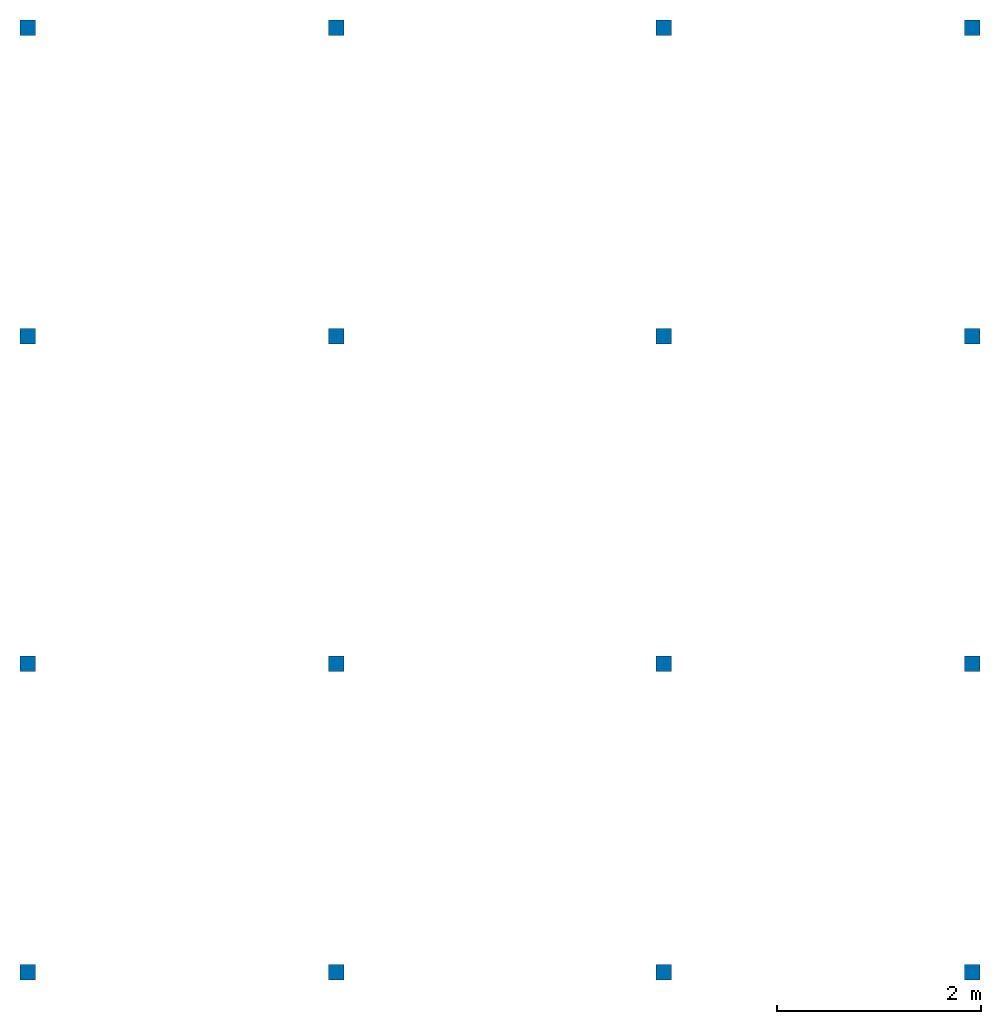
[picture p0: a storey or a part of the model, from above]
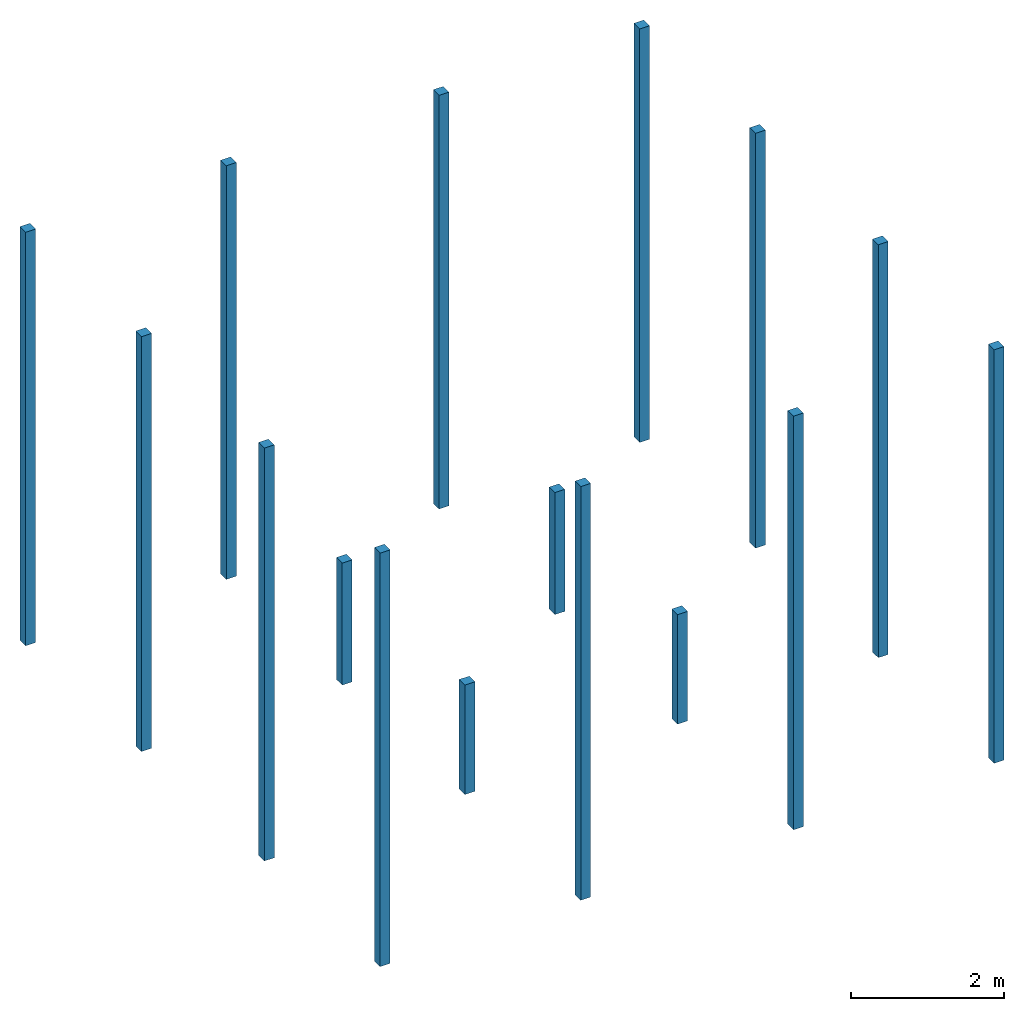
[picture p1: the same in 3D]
Properties of the parts of a building model (IFC2X3), part 1 of 2

# File
Description: ViewDefinition [CoordinationView_V2.0, QuantityTakeOffAddOnView], RevitIdentifiers [ContentGUID: 1b7e957a-3815-4cde-909e-a2956a1124d2, VersionGUID: 607071c9-a920-4b14-b0dc-eb4321b22190, NumberOfSaves: 63], CoordinateReference [CoordinateBase: Coordenadas compartidas, ProjectSite: Default Site]
File name: 20261019_WorkshopBIM-IA_AlbertoJercicM_.ifc
Time: 2026-10-19T21:17:42-04:00
Written by: ODA SDAI 24.12
Made in: Autodesk Revit 25.4.41.14 (ESP) - IFC 25.4.41.14

# IfcProject, TBC-AJ-01
LongName: Habitáculo y Refugio Turístico Magallanes; Phase: Caso de Estudio Académico

# IfcSite, Default
RefLatitude: 42, 21, 31, 181945; RefLongitude: -71, -3, -24, -263305; RefElevation: 0 cm
Otros - Categoría: Información de proyecto; Dirección de proyecto: Tierra del Fuego, Región de Magallanes, Chile.; Estado de proyecto: Caso de Estudio Académico; Fecha de emisión de proyecto: 2026; Nombre de cliente: The BIM COWORK; Nombre de proyecto: Habitáculo y Refugio Turístico Magallanes; Número de proyecto: TBC-AJ-01
Datos de identidad - Autor: CASO DE ESTUDIO — Únicamente con fines académicos. No apto para construcción. Proyecto liberado por caso de estudio TBC.; Descripción de organización: Estudiante: Arq Alberto Jercic | Curso: BIM Aplicado — Módulo IV | CASO DE ESTUDIO — Únicamente con fines académicos. No apto para construcción. Proyecto liberado por caso de estudio TBC.; Nombre del edificio: Workshop Hbaitáculo - Refugio Tierra del Fuego; Nombre de organización: The Bim Cowork

# IfcSite: Sólido topográfico:Sólido topográfico 1, Sólido topográfico:Sólido topográfico 1:651923
Type - Material: Earth 250 cm
Type - Otros - Categoría: Sólido topográfico; Nombre de familia: Sólido topográfico
Type - Construcción - Grosor predeterminado: 250 cm
Type - Gráficos - Color de relleno de detalle bajo: 0
Type - Datos de identidad - Descripción: Terreno / emplazamiento.; Marca de tipo: TP1; Nombre de tipo: Sólido topográfico 1; Nota clave: TP1
Type - Propiedades analíticas - Absortancia: 0.1; Aspereza: 1; Coeficiente de transferencia de calor (U): 0.3348 kg/s3/K; Masa térmica: 3399500 kg/K/s2; Resistencia térmica (R): 2.98686 s3*K/kg
Pset_LandRegistration - LandTitleID: S/I
Pset_PropertyAgreement - Restrictions: S/I
Pset_SiteCommon - SeismicClassification: S/I
BaseQuantities - GrossArea: 40.8669 m2
Otros - Familia: Sólido topográfico; Familia y tipo: Sólido topográfico: Sólido topográfico 1; ID de tipo: 421453; Tipo: Sólido topográfico 1
Restricciones - Delimitación de habitación: yes; Relacionado con masa: no; Desfase de altura desde nivel: 0 cm; Nivel: NTN
Datos - NDI: NDI-1
Cotas - Área: 576.228 m2; Elevación en parte inferior: -250 cm; Perímetro: 9600 cm; Volumen: 935.852 m3
Proceso por fases - Fase de creación: New Construction
Edición de forma de losa - Condición de borde curvado: 0

# IfcBuilding, Workshop Hbaitáculo - Refugio Tierra del Fuego
LongName: Workshop Hbaitáculo - Refugio Tierra del Fuego
Otros - Categoría: Información de proyecto; Dirección de proyecto: Tierra del Fuego, Región de Magallanes, Chile.; Estado de proyecto: Caso de Estudio Académico; Fecha de emisión de proyecto: 2026; Nombre de cliente: The BIM COWORK; Nombre de proyecto: Habitáculo y Refugio Turístico Magallanes; Número de proyecto: TBC-AJ-01
Datos de identidad - Autor: CASO DE ESTUDIO — Únicamente con fines académicos. No apto para construcción. Proyecto liberado por caso de estudio TBC.; Descripción de organización: Estudiante: Arq Alberto Jercic | Curso: BIM Aplicado — Módulo IV | CASO DE ESTUDIO — Únicamente con fines académicos. No apto para construcción. Proyecto liberado por caso de estudio TBC.; Nombre del edificio: Workshop Hbaitáculo - Refugio Tierra del Fuego; Nombre de organización: The Bim Cowork

# IfcBuildingStorey: Nivel:TBC-NIVEL (6)
In: Workshop Hbaitáculo - Refugio Tierra del Fuego
Otros - Categoría: Niveles; Familia: Nivel; Familia y tipo: Nivel: TBC-NIVEL; ID de tipo: 365066; Tipo: TBC-NIVEL
Cotas - Altura de cálculo: 0 cm
Datos de identidad - Estructura: no; Planta de edificio: yes
Otros(Tipo) - Categoría: Niveles; Nombre de familia: Nivel
Restricciones(Tipo) - Base de elevación: Punto base del proyecto
Gráficos(Tipo) - Color: 8421504; Grosor de línea: 1; Patrón de línea: Centre; Símbolo: NVL_Cabezal Nivel Triangulo1 : 2,0 mm; Símbolo en extremo 1 por defecto: yes; Símbolo en extremo 2 por defecto: no
Datos de identidad(Tipo) - Nombre de tipo: TBC-NIVEL
Name | LongName = Nombre | Elevation (cm) = Elevación (cm)
NOG_BASE PILARES | NOG_BASE PILARES | -180
NTN | NTN | 0
NOG_PISO 1 | NOG_PISO 1 | 100
NPT | NPT | 123
NOG_SIP Cara Superior | NOG_SIP Cara Superior | 421
NOG_Pilares Cara Superior | NOG_Pilares Cara Superior | 601

# IfcSpace: Baño 1 2:740895, 2
In: NPT
LongName: Baño 1; InteriorOrExteriorSpace: INTERNAL
Pset_SpaceCommon - IsExternal: no
Pset_SpaceFireSafetyRequirements - FireRiskFactor: Sin informacion
BaseQuantities - GrossFloorArea: 1.95108 m2; NetFloorArea: 1.95108 m2; GrossCeilingArea: 1.95108 m2; Height: 295.421 cm; GrossVolume: 5.76388 m3
Otros - Categoría: Habitaciones; ID de fase: 86961
Restricciones - Desfase de base: 0 cm; Límite superior: NOG_SIP Cara Superior; Desfase de límite: -2.57916 cm; Nivel: NPT
Datos - NDI: NDI-1
Cotas - Altura de cálculo: 0 cm; Altura sin límites: 295.421 cm; Área: 1.95108 m2; Perímetro: 561 cm; Volumen: 5.76388 m3
Análisis energético - Carga de iluminación base en: Por tipo de espacio; Carga de iluminación especificada: 0 W; Carga de iluminación real: 0 W; Carga de potencia base de diseño en: Por tipo de espacio; Carga de potencia especificada: 0 W; Carga de potencia real: 0 W; Contribución de iluminación de plénum: 0.2; Número de personas: 0; Unidades de carga de iluminación: Densidad de potencia; Unidades de carga de potencia: Densidad de potencia; Valores de carga de calor: Por tipo de espacio; Área por persona: 28.5714 m2; Carga de iluminación especificada por área: 10.7639 kg/s3; Carga de iluminación real por área: 0 kg/s3; Carga de potencia especificada por área: 13.9931 kg/s3; Carga de potencia real por área: 0 kg/s3; Incremento de calor latente por persona: 58.6142 W; Incremento de calor sensible por persona: 73.2678 W; Incremento de calor total por persona: 131.882 W
Datos de identidad - Altura: 295.421 cm; Area bruta del espacio: 1.95108 m2; Area neta del espacio: 1.95108 m2; Factor de riesgo de incendio: Sin informacion; Nombre: Baño 1; Nombre descriptivo del espacio: BANO_1; Nombre o codigo del Espacio: 2; Número: 2; Perimetro: 561 cm; Volumen: 5.76388 m3
Proceso por fases - Fase: New Construction
Texto - Descripción Acabado de Cielo: Cielo Placa Volcanita ST + Melamina; Descripción Acabado de Muros: Rev. Porcelanato ZH; Descripción Acabado de Piso: PAV Tipo Porcelanato 1; Descripción Guardapolvo: No considera

# IfcSpace: Baño 2 3:740898, 3
In: NPT
LongName: Baño 2; InteriorOrExteriorSpace: INTERNAL
Pset_SpaceCommon - IsExternal: no
Pset_SpaceFireSafetyRequirements - FireRiskFactor: Sin informacion
BaseQuantities - GrossFloorArea: 1.9488 m2; NetFloorArea: 1.9488 m2; GrossCeilingArea: 1.9488 m2; Height: 295.616 cm; GrossVolume: 5.7587 m3
Otros - Categoría: Habitaciones; ID de fase: 86961
Restricciones - Desfase de base: 0 cm; Límite superior: NOG_SIP Cara Superior; Desfase de límite: -2.3836 cm; Nivel: NPT
Datos - NDI: NDI-1
Cotas - Altura de cálculo: 0 cm; Altura sin límites: 295.616 cm; Área: 1.9488 m2; Perímetro: 561 cm; Volumen: 5.7587 m3
Análisis energético - Carga de iluminación base en: Por tipo de espacio; Carga de iluminación especificada: 0 W; Carga de iluminación real: 0 W; Carga de potencia base de diseño en: Por tipo de espacio; Carga de potencia especificada: 0 W; Carga de potencia real: 0 W; Contribución de iluminación de plénum: 0.2; Número de personas: 0; Unidades de carga de iluminación: Densidad de potencia; Unidades de carga de potencia: Densidad de potencia; Valores de carga de calor: Por tipo de espacio; Área por persona: 28.5714 m2; Carga de iluminación especificada por área: 10.7639 kg/s3; Carga de iluminación real por área: 0 kg/s3; Carga de potencia especificada por área: 13.9931 kg/s3; Carga de potencia real por área: 0 kg/s3; Incremento de calor latente por persona: 58.6142 W; Incremento de calor sensible por persona: 73.2678 W; Incremento de calor total por persona: 131.882 W
Datos de identidad - Altura: 295.616 cm; Area bruta del espacio: 1.9488 m2; Area neta del espacio: 1.9488 m2; Factor de riesgo de incendio: Sin informacion; Nombre: Baño 2; Nombre descriptivo del espacio: BANO_2; Nombre o codigo del Espacio: 3; Número: 3; Perimetro: 561 cm; Volumen: 5.7587 m3
Proceso por fases - Fase: New Construction
Texto - Descripción Acabado de Cielo: Cielo Placa Volcanita ST + Melamina; Descripción Acabado de Muros: Rev. Porcelanato ZH; Descripción Acabado de Piso: PAV Tipo Porcelanato 1; Descripción Guardapolvo: No considera

# IfcSpace: Cocina 4:741249, 4
In: NPT
LongName: Cocina; InteriorOrExteriorSpace: INTERNAL
Pset_SpaceCommon - IsExternal: no
Pset_SpaceFireSafetyRequirements - FireRiskFactor: Sin informacion
BaseQuantities - GrossFloorArea: 8.67247 m2; NetFloorArea: 8.67247 m2; GrossCeilingArea: 8.67247 m2; Height: 298 cm
Otros - Categoría: Habitaciones; ID de fase: 86961
Restricciones - Desfase de base: 0 cm; Límite superior: NOG_SIP Cara Superior; Desfase de límite: 0 cm; Nivel: NPT
Datos - NDI: NDI-1
Cotas - Altura de cálculo: 0 cm; Altura sin límites: 298 cm; Área: 8.67247 m2; Perímetro: 1179.9 cm; Volumen: 22.599 m3
Análisis energético - Carga de iluminación base en: Por tipo de espacio; Carga de iluminación especificada: 0 W; Carga de iluminación real: 0 W; Carga de potencia base de diseño en: Por tipo de espacio; Carga de potencia especificada: 0 W; Carga de potencia real: 0 W; Contribución de iluminación de plénum: 0.2; Número de personas: 0; Unidades de carga de iluminación: Densidad de potencia; Unidades de carga de potencia: Densidad de potencia; Valores de carga de calor: Por tipo de espacio; Área por persona: 28.5714 m2; Carga de iluminación especificada por área: 10.7639 kg/s3; Carga de iluminación real por área: 0 kg/s3; Carga de potencia especificada por área: 13.9931 kg/s3; Carga de potencia real por área: 0 kg/s3; Incremento de calor latente por persona: 58.6142 W; Incremento de calor sensible por persona: 73.2678 W; Incremento de calor total por persona: 131.882 W
Datos de identidad - Altura: 298 cm; Area bruta del espacio: 8.67247 m2; Area neta del espacio: 8.67247 m2; Factor de riesgo de incendio: Sin informacion; Nombre: Cocina; Nombre descriptivo del espacio: COCINA; Nombre o codigo del Espacio: 4; Número: 4; Perimetro: 1179.9 cm; Volumen: 22.599 m3
Proceso por fases - Fase: New Construction
Texto - Descripción Acabado de Cielo: Cielo Placa Volcanita ST + Melamina; Descripción Acabado de Muros: Rev. Melamina tipo madera; Descripción Acabado de Piso: PAV Tipo Madera; Descripción Guardapolvo: No considera

# IfcSpace: Espacio central 1:740673, 1
In: NPT
LongName: Espacio central; InteriorOrExteriorSpace: INTERNAL
Pset_SpaceCommon - IsExternal: no
Pset_SpaceFireSafetyRequirements - FireRiskFactor: Sin informacion
BaseQuantities - GrossFloorArea: 53.2464 m2; NetFloorArea: 53.2464 m2; GrossCeilingArea: 53.2464 m2; Height: 295 cm; GrossVolume: 157.077 m3
Otros - Categoría: Habitaciones; ID de fase: 86961
Restricciones - Desfase de base: 0 cm; Desfase de límite: -3 cm; Límite superior: NOG_SIP Cara Superior; Nivel: NPT
Datos - NDI: NDI-1
Cotas - Altura de cálculo: 0 cm; Altura sin límites: 295 cm; Área: 53.2464 m2; Perímetro: 5125.3 cm; Volumen: 157.077 m3
Análisis energético - Área por persona: 28.5714 m2; Carga de iluminación base en: Por tipo de espacio; Carga de iluminación especificada: 0 W; Carga de iluminación especificada por área: 10.7639 kg/s3; Carga de iluminación real: 0 W; Carga de iluminación real por área: 0 kg/s3; Carga de potencia base de diseño en: Por tipo de espacio; Carga de potencia especificada: 0 W; Carga de potencia especificada por área: 13.9931 kg/s3; Carga de potencia real: 0 W; Carga de potencia real por área: 0 kg/s3; Contribución de iluminación de plénum: 0.2; Incremento de calor latente por persona: 58.6142 W; Incremento de calor sensible por persona: 73.2678 W; Incremento de calor total por persona: 131.882 W; Número de personas: 0; Unidades de carga de iluminación: Densidad de potencia; Unidades de carga de potencia: Densidad de potencia; Valores de carga de calor: Por tipo de espacio
Datos de identidad - Altura: 295 cm; Area bruta del espacio: 53.2464 m2; Area neta del espacio: 53.2464 m2; Factor de riesgo de incendio: Sin informacion; Nombre: Espacio central; Nombre descriptivo del espacio: ESPACIO_CENTRAL; Nombre o codigo del Espacio: 1; Número: 1; Perimetro: 5125.3 cm; Volumen: 157.077 m3
Proceso por fases - Fase: New Construction
Texto - Descripción Acabado de Cielo: Cielo Placa Volcanita ST + Melamina; Descripción Acabado de Muros: Rev. Melamina tipo madera; Descripción Acabado de Piso: PAV Tipo Madera; Descripción Guardapolvo: No considera

# IfcBeam: Arauco Hilam Viga:Hilam Viga 65x228 mm (53)
Type - PredefinedType: BEAM
Type - Otros - Categoría: Armazón estructural; Nombre de familia: Arauco Hilam Viga
Type - Cotas - CA_Ancho: 22.8 cm; CA_Espesor: 6.5 cm; CA_Largo: 800 cm
Type - Datos de identidad - Ca_Ancho: 228mm; ca_Certificaciones: Norma Chilena NCh2148; ca_Código_Catálogo_Arquitectura: 231_ARA_017; ca_Contacto: Especificaciones@arauco.cl; ca_Creado_por: Catálogo Arquitectura; ca_Especificaciones_Técnicas: Hilam Estándar es una línea de productos de ingeniería para la construcción, conformada por elementos de madera laminada de sección estándar que se complementa con otros productos de madera y tableros de ARAUCO®. Además, se puede usar en estructuras mixtas, combinado con otros materiales como hormigón armado y acero.; Ca_Espesores: 65mm; ca_Fabricante: Arauco; Ca_Instalación: No se especifica; ca_Itemizado_CDT: C 06 02 00; Ca_Largo: 8m; ca_MasterFormat®: 06 18 13; ca_Países_de_distribución: Ar/Au/Ch/Co/EU/Me/Pe/USA/Ca; Ca_Peso: 65kg; Ca_Piezas por paquete: 20; ca_Producto: Hilam Viga 65x228mm; ca_Representante: Arauco; ca_Teléfono: 56 2 24617 200; Ca_Usos: Vigas de piso y techo. Pilares a la vista. Pérgolas. Cobertizos. Escaleras. Decoración. Area industrial.; ca_Web_del_fabricante: www.arauco.cl; ca_Web_del_Representante: www.arauco.cl; Descripción: Viga madera laminada encolada Hilam 65x228 mm NCh2148. Madera expuesta con tratamiento: protector impregnante / stain (uso general exterior) Ceresita Cerestain.; Marca de tipo: VG1; Nombre de tipo: Hilam Viga 65x228 mm; Nota clave: VIG; Número OmniClass: 23.25.30.11.14.14; Título OmniClass: Beams
Type - Estructura - Forma de sección: 0
Material: Madera Oscura
BaseQuantities - CrossSectionArea: 0.01482 m2
Pset_BeamCommon - FireRating: S/I; LoadBearing: yes; Status: NEW
Otros - Familia: Arauco Hilam Viga; Familia y tipo: Arauco Hilam Viga: Hilam Viga 65x228 mm; ID de tipo: 581389; Tipo: Hilam Viga 65x228 mm
Restricciones - Rotación de sección transversal: 0 deg
Datos - NDI: NDI-1
Datos de identidad - Tiene asociación: no
Materiales y acabados - Material estructural: Madera Oscura
Proceso por fases - Fase de creación: New Construction
Estructura - Recubrimiento de armadura - Cara inferior: Rebar Cover 1 <25 mm>; Recubrimiento de armadura - Cara superior: Rebar Cover 1 <25 mm>; Recubrimiento de armadura - Otras caras: Rebar Cover 1 <25 mm>; Uso estructural: Otro
Posición geométrica - Estado de unión: Ambas uniones activadas; Justificación Y: Origen; Justificación YZ: Uniforme; Justificación Z: Parte superior; Valor de desfase Y: 0 cm; Valor de desfase Z: 0 cm
Name (Arauco Hilam Viga:Hilam Viga 65x228 mm:...) | In | Length (cm) = Longitud de corte (cm) | OuterSurfaceArea (m2) | GrossVolume (m3) = NetVolume (m3) = Volumen (m3) | Desfase de nivel final (cm) | Desfase de nivel inicial (cm) | Elevación de nivel de referencia (cm) | Nivel de referencia | Elevación en parte inferior (cm) | Elevación en parte superior (cm) | Longitud (cm) | Extensión final (cm) | Extensión inicial (cm)
581417 | NOG_PISO 1 | 930 | 5.4498 | 0.137826 | 0 | 0 | 100 | NOG_PISO 1 | 77.2 | 100 | 961.251 | 0 | -31.2511 | Restricciones - Orientación: Normal; Plano de trabajo: Nivel : NOG_PISO 1
581750 | NOG_PISO 1 | 930 | 5.4498 | 0.137826 | 0 | 0 | 100 | NOG_PISO 1 | 77.2 | 100 | 961.251 | 0 | -31.2511 | Restricciones - Orientación: Normal; Plano de trabajo: Nivel : NOG_PISO 1
581929 | NOG_PISO 1 | 318.25 | 1.86494 | 0.0471646 | 0 | 0 | 100 | NOG_PISO 1 | 77.2 | 100 | 349.501 | 0 | -31.2511 | Restricciones - Orientación: Normal; Plano de trabajo: Nivel : NOG_PISO 1
581937 | NOG_PISO 1 | 318.25 | 1.86494 | 0.0471646 | 0 | 0 | 100 | NOG_PISO 1 | 77.2 | 100 | 349.501 | 0 | -31.2511 | Restricciones - Orientación: Normal; Plano de trabajo: Nivel : NOG_PISO 1
581945 | NOG_PISO 1 | 318.25 | 1.86494 | 0.0471646 | 0 | 0 | 100 | NOG_PISO 1 | 77.2 | 100 | 349.501 | 0 | -31.2511 | Restricciones - Orientación: Normal; Plano de trabajo: Nivel : NOG_PISO 1
582254 | NOG_PISO 1 | 930 | 5.4498 | 0.137826 | 0 | 0 | 100 | NOG_PISO 1 | 77.2 | 100 | 961.251 | 0 | -31.2511 | Restricciones - Orientación: Normal; Plano de trabajo: Nivel : NOG_PISO 1
582255 | NOG_PISO 1 | 930 | 5.4498 | 0.137826 | 0 | 0 | 100 | NOG_PISO 1 | 77.2 | 100 | 961.251 | 0 | -31.2511 | Restricciones - Orientación: Normal; Plano de trabajo: Nivel : NOG_PISO 1
582256 | NOG_PISO 1 | 930 | 5.4498 | 0.137826 | 0 | 0 | 100 | NOG_PISO 1 | 77.2 | 100 | 961.251 | 0 | -31.2511 | Restricciones - Orientación: Normal; Plano de trabajo: Nivel : NOG_PISO 1
582427 | NOG_PISO 1 | 930 | 5.4498 | 0.137826 | 0 | 0 | 100 | NOG_PISO 1 | 77.2 | 100 | 961.251 | 0 | -31.2511 | Restricciones - Orientación: Normal; Plano de trabajo: Nivel : NOG_PISO 1
582686 | NOG_PISO 1 | 930 | 5.4498 | 0.137826 | 0 | 0 | 100 | NOG_PISO 1 | 77.2 | 100 | 961.251 | 0 | -31.2511 | Restricciones - Orientación: Normal; Plano de trabajo: Nivel : NOG_PISO 1
582687 | NOG_PISO 1 | 930 | 5.4498 | 0.137826 | 0 | 0 | 100 | NOG_PISO 1 | 77.2 | 100 | 961.251 | 0 | -31.2511 | Restricciones - Orientación: Normal; Plano de trabajo: Nivel : NOG_PISO 1
582688 | NOG_PISO 1 | 930 | 5.4498 | 0.137826 | 0 | 0 | 100 | NOG_PISO 1 | 77.2 | 100 | 961.251 | 0 | -31.2511 | Restricciones - Orientación: Normal; Plano de trabajo: Nivel : NOG_PISO 1
582689 | NOG_PISO 1 | 930 | 5.4498 | 0.137826 | 0 | 0 | 100 | NOG_PISO 1 | 77.2 | 100 | 961.251 | 0 | -31.2511 | Restricciones - Orientación: Normal; Plano de trabajo: Nivel : NOG_PISO 1
582690 | NOG_PISO 1 | 930 | 5.4498 | 0.137826 | 0 | 0 | 100 | NOG_PISO 1 | 77.2 | 100 | 961.251 | 0 | -31.2511 | Restricciones - Orientación: Normal; Plano de trabajo: Nivel : NOG_PISO 1
583638 | NOG_PISO 1 | 966.668 | 5.66467 | 0.14326 | -22.8 | -22.8 | 100 | NOG_PISO 1 | 54.4 | 77.2 | 952 | -9.89385 | 24.5614
584148 | NOG_PISO 1 | 956.862 | 5.60721 | 0.141807 | -45.6 | -45.6 | 100 | NOG_PISO 1 | 31.6 | 54.4 | 1110 | -87.3622 | -65.7763
589290 | NOG_PISO 1 | 956.862 | 5.60721 | 0.141807 | -45.6 | -45.6 | 100 | NOG_PISO 1 | 31.6 | 54.4 | 1110 | -87.3622 | -65.7763
589528 | NOG_PISO 1 | 966.668 | 5.66467 | 0.14326 | -22.8 | -22.8 | 100 | NOG_PISO 1 | 54.4 | 77.2 | 952 | -9.89385 | 24.5614
589572 | NOG_PISO 1 | 966.668 | 5.66467 | 0.14326 | -22.8 | -22.8 | 100 | NOG_PISO 1 | 54.4 | 77.2 | 952 | -9.89385 | 24.5614
589573 | NOG_PISO 1 | 966.668 | 5.66467 | 0.14326 | -22.8 | -22.8 | 100 | NOG_PISO 1 | 54.4 | 77.2 | 952 | -9.89385 | 24.5614
589663 | NOG_PISO 1 | 956.862 | 5.60721 | 0.141807 | -45.6 | -45.6 | 100 | NOG_PISO 1 | 31.6 | 54.4 | 1110 | -87.3622 | -65.7763
589673 | NOG_PISO 1 | 956.862 | 5.60721 | 0.141807 | -45.6 | -45.6 | 100 | NOG_PISO 1 | 31.6 | 54.4 | 1110 | -87.3622 | -65.7763
593334 | NOG_SIP Cara Superior | 956.862 | 5.60721 | 0.141807 | 107.2 | 107.2 | 421 | NOG_SIP Cara Superior | 505.4 | 528.2 | 1110 | -87.3622 | -65.7763
593451 | NOG_Pilares Cara Superior | 956.862 | 5.60721 | 0.141807 | -22.8 | -22.8 | 601 | NOG_Pilares Cara Superior | 555.4 | 578.2 | 1110 | -87.3622 | -65.7763
593488 | NOG_PISO 1 | 1184.63 | 6.94193 | 0.175562 | 502 | 452 | 100 | NOG_PISO 1 |  |  | 953.312 | 98.1433 | 133.175
594363 | NOG_Pilares Cara Superior | 1026.86 | 6.01741 | 0.152181 | -40 | -40 | 601 | NOG_Pilares Cara Superior | 538.2 | 561 | 1110 | -17.3622 | -65.7763
594373 | NOG_Pilares Cara Superior | 956.862 | 5.60721 | 0.141807 | -55.5 | -55.5 | 601 | NOG_Pilares Cara Superior | 522.7 | 545.5 | 1110 | -87.3622 | -65.7763
595492 | NOG_PISO 1 | 1093 | 6.40498 | 0.161983 | 491.21 | 491.21 | 100 | NOG_PISO 1 | 568.41 | 591.21 | 961.251 | 163 | -31.2511
595493 | NOG_PISO 1 | 1093 | 6.40498 | 0.161983 | 503.02 | 503.02 | 100 | NOG_PISO 1 | 580.22 | 603.02 | 961.251 | 163 | -31.2511
595494 | NOG_PISO 1 | 1093 | 6.40498 | 0.161983 | 499.08 | 499.08 | 100 | NOG_PISO 1 | 576.28 | 599.08 | 961.251 | 163 | -31.2511
595495 | NOG_PISO 1 | 1093 | 6.40498 | 0.161983 | 495.14 | 495.14 | 100 | NOG_PISO 1 | 572.34 | 595.14 | 961.251 | 163 | -31.2511
595496 | NOG_PISO 1 | 1093 | 6.40498 | 0.161983 | 487.53 | 487.53 | 100 | NOG_PISO 1 | 564.73 | 587.53 | 961.251 | 163 | -31.2511
595497 | NOG_PISO 1 | 1093 | 6.40498 | 0.161983 | 483.85 | 483.85 | 100 | NOG_PISO 1 | 561.05 | 583.85 | 961.251 | 163 | -31.2511
595498 | NOG_PISO 1 | 1093 | 6.40498 | 0.161983 | 480.18 | 480.18 | 100 | NOG_PISO 1 | 557.38 | 580.18 | 961.251 | 163 | -31.2511
595499 | NOG_PISO 1 | 1093 | 6.40498 | 0.161983 | 476.5 | 476.5 | 100 | NOG_PISO 1 | 553.7 | 576.5 | 961.251 | 163 | -31.2511
595500 | NOG_PISO 1 | 1093 | 6.40498 | 0.161983 | 506.96 | 506.96 | 100 | NOG_PISO 1 | 584.16 | 606.96 | 961.251 | 163 | -31.2511
595501 | NOG_PISO 1 | 1093 | 6.40498 | 0.161983 | 510.64 | 510.64 | 100 | NOG_PISO 1 | 587.84 | 610.64 | 961.251 | 163 | -31.2511
595502 | NOG_PISO 1 | 1093 | 6.40498 | 0.161983 | 514.31 | 514.31 | 100 | NOG_PISO 1 | 591.51 | 614.31 | 961.251 | 163 | -31.2511
595503 | NOG_PISO 1 | 1093 | 6.40498 | 0.161983 | 517.99 | 517.99 | 100 | NOG_PISO 1 | 595.19 | 617.99 | 961.251 | 163 | -31.2511
595504 | NOG_PISO 1 | 1093 | 6.40498 | 0.161983 | 521.67 | 521.67 | 100 | NOG_PISO 1 | 598.87 | 621.67 | 961.251 | 163 | -31.2511
597168 | NOG_PISO 1 | 1184.63 | 6.94193 | 0.175562 | 502 | 452 | 100 | NOG_PISO 1 |  |  | 953.312 | 98.1433 | 133.175
597174 | NOG_PISO 1 | 1184.63 | 6.94193 | 0.175562 | 502 | 452 | 100 | NOG_PISO 1 |  |  | 953.312 | 98.1433 | 133.175
597198 | NOG_PISO 1 | 1184.63 | 6.94193 | 0.175562 | 502 | 452 | 100 | NOG_PISO 1 |  |  | 953.312 | 98.1433 | 133.175
598141 | NOG_PISO 1 | 1093 | 6.40498 | 0.161983 | 472.82 | 472.82 | 100 | NOG_PISO 1 | 550.02 | 572.82 | 961.251 | 163 | -31.2511
598283 | NOG_PISO 1 | 1093 | 6.40498 | 0.161983 | 469.15 | 469.15 | 100 | NOG_PISO 1 | 546.35 | 569.15 | 961.251 | 163 | -31.2511
598472 | NOG_PISO 1 | 1093 | 6.40498 | 0.161983 | 525.34 | 525.34 | 100 | NOG_PISO 1 | 602.54 | 625.34 | 961.251 | 163 | -31.2511
598478 | NOG_PISO 1 | 1093 | 6.40498 | 0.161983 | 529.02 | 529.02 | 100 | NOG_PISO 1 | 606.22 | 629.02 | 961.251 | 163 | -31.2511
637849 | NOG_PISO 1 | 318.25 | 1.86494 | 0.0471646 | 0 | 0 | 100 | NOG_PISO 1 | 77.2 | 100 | 318.25 | 0 | 0 | Restricciones - Orientación: Normal; Plano de trabajo: Nivel : NOG_PISO 1
637916 | NOG_PISO 1 | 318.25 | 1.86494 | 0.0471646 | 0 | 0 | 100 | NOG_PISO 1 | 77.2 | 100 | 441.251 | 0 | -123.001 | Restricciones - Orientación: Normal; Plano de trabajo: Nivel : NOG_PISO 1
638011 | NOG_PISO 1 | 318.25 | 1.86494 | 0.0471646 | 0 | 0 | 100 | NOG_PISO 1 | 77.2 | 100 | 318.25 | 0 | 0 | Restricciones - Orientación: Normal; Plano de trabajo: Nivel : NOG_PISO 1
658531 | NOG_SIP Cara Superior | 966.668 | 5.66467 | 0.14326 | 84.4 | 84.4 | 421 | NOG_SIP Cara Superior | 482.6 | 505.4 | 952 | -9.89385 | 24.5614
658533 | NOG_SIP Cara Superior | 956.862 | 5.60721 | 0.141807 | 61.6 | 61.6 | 421 | NOG_SIP Cara Superior | 459.8 | 482.6 | 1110 | -87.3622 | -65.7763
658534 | NOG_SIP Cara Superior | 966.668 | 5.66467 | 0.14326 | 84.4 | 84.4 | 421 | NOG_SIP Cara Superior | 482.6 | 505.4 | 952 | -9.89385 | 24.5614

# IfcBuildingElementProxy: 60cm_gas_on_glass_hob:Default, 60cm_gas_on_glass_hob:Default:668263
In: 4
Type - Material: 88a7dab3_c516_465e_ae32_d9534398d1b3, 32bea116_7d50_41af_a57c_76851e703032, f31bdfdc_01d2_46e0_822c_941099069146
Type - Otros - Categoría: Modelos genéricos; BOS_0_127_127_127_Visibility: no; BOS_0_Blue: 127; BOS_0_Green: 127; BOS_0_Material: 599a3f79_6c79_439e_8cac_d266d0c92df2; BOS_0_Native_Visibility: yes; BOS_0_Red: 127; BOS_0_Visibility: 1; BOS_1_127_127_127_Visibility: no; BOS_1_Blue: 127; BOS_1_Green: 127; BOS_1_Material: 88a7dab3_c516_465e_ae32_d9534398d1b3; BOS_1_Native_Visibility: yes; BOS_1_Red: 127; BOS_1_Visibility: 1; BOS_10_127_127_127_Visibility: no; BOS_10_Blue: 127; BOS_10_Green: 127; BOS_10_Material: 32bea116_7d50_41af_a57c_76851e703032; BOS_10_Native_Visibility: yes; BOS_10_Red: 127; BOS_10_Visibility: 1; BOS_11_127_127_127_Visibility: no; BOS_11_Blue: 127; BOS_11_Green: 127; BOS_11_Material: 88a7dab3_c516_465e_ae32_d9534398d1b3; BOS_11_Native_Visibility: yes; BOS_11_Red: 127; BOS_11_Visibility: 1; BOS_12_127_127_127_Visibility: no; BOS_12_Blue: 127; BOS_12_Green: 127; BOS_12_Material: 88a7dab3_c516_465e_ae32_d9534398d1b3; BOS_12_Native_Visibility: yes; BOS_12_Red: 127; BOS_12_Visibility: 1; BOS_13_127_127_127_Visibility: no; BOS_13_Blue: 127; BOS_13_Green: 127; BOS_13_Material: 32bea116_7d50_41af_a57c_76851e703032; BOS_13_Native_Visibility: yes; BOS_13_Red: 127; BOS_13_Visibility: 1; BOS_14_127_127_127_Visibility: no; BOS_14_Blue: 127; BOS_14_Green: 127; BOS_14_Material: f31bdfdc_01d2_46e0_822c_941099069146; BOS_14_Native_Visibility: yes; BOS_14_Red: 127; BOS_14_Visibility: 1; BOS_15_127_127_127_Visibility: no; BOS_15_Blue: 127; BOS_15_Green: 127; BOS_15_Material: 32bea116_7d50_41af_a57c_76851e703032; BOS_15_Native_Visibility: yes; BOS_15_Red: 127; BOS_15_Visibility: 1; BOS_16_127_127_127_Visibility: no; BOS_16_Blue: 127; BOS_16_Green: 127; BOS_16_Material: f31bdfdc_01d2_46e0_822c_941099069146; BOS_16_Native_Visibility: yes; BOS_16_Red: 127; BOS_16_Visibility: 1; BOS_17_127_127_127_Visibility: no; BOS_17_Blue: 127; BOS_17_Green: 127; BOS_17_Material: 88a7dab3_c516_465e_ae32_d9534398d1b3; BOS_17_Native_Visibility: yes; BOS_17_Red: 127; BOS_17_Visibility: 1; BOS_18_127_127_127_Visibility: no; BOS_18_Blue: 127; BOS_18_Green: 127; BOS_18_Material: 88a7dab3_c516_465e_ae32_d9534398d1b3; BOS_18_Native_Visibility: yes; BOS_18_Red: 127; BOS_18_Visibility: 1; BOS_19_127_127_127_Visibility: no; BOS_19_Blue: 127; BOS_19_Green: 127; BOS_19_Material: 88a7dab3_c516_465e_ae32_d9534398d1b3; BOS_19_Native_Visibility: yes; BOS_19_Red: 127; BOS_19_Visibility: 1; BOS_2_127_127_127_Visibility: no; BOS_2_Blue: 127; BOS_2_Green: 127; BOS_2_Material: 88a7dab3_c516_465e_ae32_d9534398d1b3; BOS_2_Native_Visibility: yes; BOS_2_Red: 127; BOS_2_Visibility: 1; BOS_20_127_127_127_Visibility: no; BOS_20_Blue: 127; BOS_20_Green: 127; BOS_20_Material: 32bea116_7d50_41af_a57c_76851e703032; BOS_20_Native_Visibility: yes; BOS_20_Red: 127; BOS_20_Visibility: 1; BOS_21_127_127_127_Visibility: no; BOS_21_Blue: 127; BOS_21_Green: 127; BOS_21_Material: 32bea116_7d50_41af_a57c_76851e703032; BOS_21_Native_Visibility: yes; BOS_21_Red: 127; BOS_21_Visibility: 1; BOS_22_127_127_127_Visibility: no; BOS_22_Blue: 127; BOS_22_Green: 127; BOS_22_Material: 88a7dab3_c516_465e_ae32_d9534398d1b3; BOS_22_Native_Visibility: yes; BOS_22_Red: 127; BOS_22_Visibility: 1; BOS_23_127_127_127_Visibility: no; BOS_23_Blue: 127; BOS_23_Green: 127; BOS_23_Material: 32bea116_7d50_41af_a57c_76851e703032; BOS_23_Native_Visibility: yes; BOS_23_Red: 127; BOS_23_Visibility: 1; BOS_24_127_127_127_Visibility: no; BOS_24_Blue: 127; BOS_24_Green: 127; BOS_24_Material: 32bea116_7d50_41af_a57c_76851e703032; BOS_24_Native_Visibility: yes; BOS_24_Red: 127; BOS_24_Visibility: 1; BOS_25_127_127_127_Visibility: no; BOS_25_Blue: 127; BOS_25_Green: 127; BOS_25_Material: 32bea116_7d50_41af_a57c_76851e703032; BOS_25_Native_Visibility: yes; BOS_25_Red: 127; BOS_25_Visibility: 1; BOS_26_127_127_127_Visibility: no; BOS_26_Blue: 127; BOS_26_Green: 127; BOS_26_Material: 32bea116_7d50_41af_a57c_76851e703032; BOS_26_Native_Visibility: yes; BOS_26_Red: 127; BOS_26_Visibility: 1; BOS_27_127_127_127_Visibility: no; BOS_27_Blue: 127; BOS_27_Green: 127; BOS_27_Material: 32bea116_7d50_41af_a57c_76851e703032; BOS_27_Native_Visibility: yes; BOS_27_Red: 127; BOS_27_Visibility: 1; BOS_28_127_127_127_Visibility: no; BOS_28_Blue: 127; BOS_28_Green: 127; BOS_28_Material: 88a7dab3_c516_465e_ae32_d9534398d1b3; BOS_28_Native_Visibility: yes; BOS_28_Red: 127; BOS_28_Visibility: 1; BOS_29_127_127_127_Visibility: no; BOS_29_Blue: 127; BOS_29_Green: 127; BOS_29_Material: 88a7dab3_c516_465e_ae32_d9534398d1b3; BOS_29_Native_Visibility: yes; BOS_29_Red: 127; BOS_29_Visibility: 1; BOS_3_127_127_127_Visibility: no; BOS_3_Blue: 127; BOS_3_Green: 127; BOS_3_Material: 32bea116_7d50_41af_a57c_76851e703032; BOS_3_Native_Visibility: yes; BOS_3_Red: 127; BOS_3_Visibility: 1; BOS_30_127_127_127_Visibility: no; BOS_30_Blue: 127; BOS_30_Green: 127; BOS_30_Material: 32bea116_7d50_41af_a57c_76851e703032; BOS_30_Native_Visibility: yes; BOS_30_Red: 127; BOS_30_Visibility: 1; BOS_31_127_127_127_Visibility: no; BOS_31_Blue: 127; BOS_31_Green: 127; BOS_31_Material: 88a7dab3_c516_465e_ae32_d9534398d1b3; BOS_31_Native_Visibility: yes; BOS_31_Red: 127; BOS_31_Visibility: 1; BOS_32_127_127_127_Visibility: no; BOS_32_Blue: 127; BOS_32_Green: 127; BOS_32_Material: 32bea116_7d50_41af_a57c_76851e703032; BOS_32_Native_Visibility: yes; BOS_32_Red: 127; BOS_32_Visibility: 1; BOS_33_127_127_127_Visibility: no; BOS_33_Blue: 127; BOS_33_Green: 127; BOS_33_Material: 32bea116_7d50_41af_a57c_76851e703032; BOS_33_Native_Visibility: yes; BOS_33_Red: 127; BOS_33_Visibility: 1; BOS_34_127_127_127_Visibility: no; BOS_34_Blue: 127; BOS_34_Green: 127; BOS_34_Material: f31bdfdc_01d2_46e0_822c_941099069146; BOS_34_Native_Visibility: yes; BOS_34_Red: 127; BOS_34_Visibility: 1; BOS_4_127_127_127_Visibility: no; BOS_4_Blue: 127; BOS_4_Green: 127; BOS_4_Material: 32bea116_7d50_41af_a57c_76851e703032; BOS_4_Native_Visibility: yes; BOS_4_Red: 127; BOS_4_Visibility: 1; BOS_5_127_127_127_Visibility: no; BOS_5_Blue: 127; BOS_5_Green: 127; BOS_5_Material: 32bea116_7d50_41af_a57c_76851e703032; BOS_5_Native_Visibility: yes; BOS_5_Red: 127; BOS_5_Visibility: 1; BOS_6_127_127_127_Visibility: no; BOS_6_Blue: 127; BOS_6_Green: 127; BOS_6_Material: 32bea116_7d50_41af_a57c_76851e703032; BOS_6_Native_Visibility: yes; BOS_6_Red: 127; BOS_6_Visibility: 1; BOS_7_127_127_127_Visibility: no; BOS_7_Blue: 127; BOS_7_Green: 127; BOS_7_Material: 32bea116_7d50_41af_a57c_76851e703032; BOS_7_Native_Visibility: yes; BOS_7_Red: 127; BOS_7_Visibility: 1; BOS_8_127_127_127_Visibility: no; BOS_8_Blue: 127; BOS_8_Green: 127; BOS_8_Material: 32bea116_7d50_41af_a57c_76851e703032; BOS_8_Native_Visibility: yes; BOS_8_Red: 127; BOS_8_Visibility: 1; BOS_9_127_127_127_Visibility: no; BOS_9_Blue: 127; BOS_9_Green: 127; BOS_9_Material: 88a7dab3_c516_465e_ae32_d9534398d1b3; BOS_9_Native_Visibility: yes; BOS_9_Red: 127; BOS_9_Visibility: 1; BOSUseNativeGeometries: 1; Nombre de familia: 60cm_gas_on_glass_hob
Type - Restricciones - Elevación por defecto: 0 cm
Type - General - Date of publishing: 3/2/2017; Design country: Italy; Edition number: 1; Manufacturer country: Italy; Manufacturer name: KitchenAid; Nominal height: 50; Nominal width: 590; Product family: Hobs; Product group: Gas; Product name: 60cm Gas on glass hob; Product SKU: KHGD4-60510; QR code: http://bimobject.com/kitchenaid/product/KHGD4-60510; Region Africa: AO, BF, BI, BJ, BW, CD, CF, CG, CI, CM, DJ, DZ, EH, ER, ET, GA, GH, GM, GN, GQ, GW, KE, LR, LS, LY, MA, MG, ML, MR, MW, MZ, NA, NE, NG, RW, SD, SL, SN, SO, SS, SZ, TD, TG, TN, TZ, UG, ZA, ZM, ZW; Region Antarctica: TF; Region Asia: AM, AZ, BD, BN, BT, CN, GE, ID, IN, JP, KG, KH, KP, KR, KZ, LA, LK, MM, MN, MY, NP, PH, PK, TH, TJ, TM, TW, UZ, VN; Region Europe: AL, AT, BA, BE, BG, BY, CH, CY, CZ, DE, DK, EE, ES, FI, FR, GB, GR, HR, HU, IE, IS, IT, LT, LU, LV, MD, ME, MK, NL, NO, PL, PT, RO, RS, RU, SE, SI, SJ, SK, UA; Region Middle East: AE, AF, EG, IL, IQ, IR, JO, KW, LB, OM, PS, QA, SA, SY, TR, YE; Region North America: BS, BZ, CA, CR, CU, DO, GL, GT, HN, HT, JM, MX, NI, PA, PR, SV, TT, US; Region Oceania: AU, FJ, NC, NZ, PG, SB, TL, VU; Region South America: AR, BO, BR, CL, CO, EC, FK, GF, GY, PE, PY, SR, UY, VE; Weight Net (Kg): 12.5
Type - Datos de identidad - Descripción: Encimera a gas sobre vidrio, 60 cm.; EAN code: https://8003437831836; Marca de tipo: EQ1; Nombre de tipo: Default; Nota clave: EQ1; Product certification: http://docs.kitchenaid.eu/_doc/400010852275EN.pdf; Product data url: https://bimobject.com/kitchenaid/product/KHGD4-60510; Product url: http://www.kitchenaid.co.uk/major-appliances-1/gas-3/gas-on-glass-60-cm-khgd4-60510/851348938000/; Technical description: http://docs.kitchenaid.eu/_doc/PR851348938000en.pdf
Type - Materiales y acabados - Material main: Glass
Otros - Familia: 60cm_gas_on_glass_hob; Familia y tipo: 60cm_gas_on_glass_hob: Default; ID de tipo: 668616; Tipo: Default
Restricciones - Nivel: NOG_PISO 1; Se mueve con elementos cercanos: no; Anfitrión: Suelo : SIP e=210mm; Desfase desde el anfitrión: 91.9948 cm; Elevación desde el nivel: 112.995 cm
Datos - NDI: NDI-1
Cotas - Área: 0.39868 m2; Volumen: 0.0267474 m3
Proceso por fases - Fase de creación: New Construction

# IfcBuildingElementProxy: M_RPC Tree - Deciduous:Blue Berry Elder - 4.5 Meters, M_RPC Tree - Deciduous:Blue Berry Elder - 4.5 Meters:637655
In: NOG_PISO 1
Type - Material: <Unnamed>
Type - Otros - Categoría: Vegetación; Nombre de familia: M_RPC Tree - Deciduous
Type - Restricciones - Elevación por defecto: 0 cm
Type - Cotas - Altura: 450 cm
Type - Datos de identidad - Comentarios de tipo: Blue Berry Elder; Descripción: Arbol decorativo Blue Berry Elder de 4,5 m (solo entorno).; Marca de tipo: VE1; Nombre de tipo: Blue Berry Elder - 4.5 Meters; Nota clave: VE1; Número OmniClass: 23.40.05.17.24; Título OmniClass: Deciduous Trees
Type - Visualización - Apariencia de renderización: RPC-16-FWVX-4SXX-5R2N-A000-ST1L-LVER-AU; Propiedades de apariencia de renderización: {2, 15},{39, RPC-16-FWVX-4SXX-5R2N-A000-ST1L-LVER-AU},{1, 0},{1, 0},{2, 35},{1, 8},{5, Color},{1, 0},{1, 0},{3, 0.8},{3, 0.8},{3, 0.8},{1, 8},{7, BBoxMin},{1, 0},{1, 0},{1, 0},{1, 0},{1, 0},{1, 8},{7, BBoxMax},{1, 0},{1, 0},{1, 0},{1, 0},{1, 0},{2, 11},{9, RPCTypeId},{1, 0},{1, 0},{39, RPC-16-FWVX-4SXX-5R2N-A000-ST1L-LVER-AU},{1, 6},{14, RPCPlantHeight},{1, 0},{1, 0},{7, 14.7638},{2, 11},{7, keyword},{1, 0},{1, 0},{285, :Geometry:RPC:Blue-Berry Elder:Sambucus cerulea:Tall:irregularly shaped shrubs or very small trees:up to 10 m high and 20 cm in diameter. The larger of the Canadian elders; occurs in southern British Columbia in forest clearings:usually on dry open sites with gravelly or stony soils.},{2, 11},{8, category},{1, 0},{1, 0},{16, :Trees [General]},{2, 11},{12, LocalizedUID},{1, 0},{1, 0},{16, Blue-Berry Elder},{2, 14},{6, Height},{1, 0},{1, 0},{7, 14.7638},{1, 2},{16, Cast Reflections},{1, 0},{1, 0},{1, 0},{1, 2},{12, Cast Shadows},{1, 0},{1, 0},{1, 1},{1, 2},{9, Lock View},{1, 0},{1, 0},{1, 0},{1, 4},{5, ViewC},{1, 0},{1, 0},{1, 0},{2, 11},{20, AdvancedUIDefinition},{1, 0},{1, 0},{0, },{2, 11},{10, AssetLibID},{1, 0},{1, 0},{36, 4D3F6E72-3F99-4203-98E9-AF80B3C7A7A4},{2, 11},{10, BaseSchema},{1, 0},{1, 0},{9, RPCSchema},{2, 11},{12, ExchangeGUID},{1, 0},{1, 0},{0, },{1, 2},{6, Hidden},{1, 0},{1, 0},{1, 0},{1, 4},{11, RPCCategory},{1, 0},{1, 0},{1, 0},{2, 11},{8, RPCImage},{1, 0},{1, 0},{0, },{1, 4},{13, SchemaVersion},{1, 0},{1, 0},{1, 4},{2, 11},{12, UIDefinition},{1, 0},{1, 0},{0, },{2, 11},{6, UIName},{1, 0},{1, 0},{39, RPC-16-FWVX-4SXX-5R2N-A000-ST1L-LVER-AU},{2, 11},{11, VersionGUID},{1, 0},{1, 0},{9, RPCSchema},{2, 11},{9, assettype},{1, 0},{1, 0},{11, RPCGeometry},{2, 11},{11, description},{1, 0},{1, 0},{0, },{2, 11},{9, localname},{1, 0},{1, 0},{3, RPC},{2, 11},{9, localtype},{1, 0},{1, 0},{3, RPC},{1, 4},{8, revision},{1, 0},{1, 0},{1, 1},{2, 11},{9, thumbnail},{1, 0},{1, 0},{0, },{1, 4},{7, version},{1, 0},{1, 0},{1, 1},{1, 2},{20, RPC_Cast Reflections},{1, 0},{1, 0},{1, 1},{1, 2},{16, RPC_Cast Shadows},{1, 0},{1, 0},{1, 1},{1, 2},{13, RPC_Lock View},{1, 0},{1, 0},{1, 0},{1, 4},{9, RPC_ViewC},{1, 0},{1, 0},{1, 0},{21, assetlibrary_base.fbx},{1, 5},
Otros - Familia: M_RPC Tree - Deciduous; Familia y tipo: M_RPC Tree - Deciduous: Blue Berry Elder - 4.5 Meters; ID de tipo: 105479; Tipo: Blue Berry Elder - 4.5 Meters
Restricciones - Nivel: NOG_PISO 1; Anfitrión: Nivel : NOG_PISO 1; Desfase desde el anfitrión: 0 cm; Elevación desde el nivel: 0 cm; Se mueve con elementos cercanos: no
Datos - NDI: NDI-1
Proceso por fases - Fase de creación: New Construction

# IfcColumn: Pilar:150x150 mm (20)
Type - PredefinedType: COLUMN; Material: Madera Oscura
Type - Otros - Categoría: Pilares estructurales; Nombre de familia: Pilar
Type - Cotas - b: 15 cm; h: 15 cm
Type - Datos de identidad - Descripción: Pilar madera 150x150 mm. Madera expuesta con tratamiento: protector impregnante / stain (uso general exterior) Ceresita Cerestain.; Marca de tipo: PL1; Nombre de tipo: 150x150 mm; Nota clave: PIL
Type - Estructura - Forma de sección: 0
BaseQuantities - CrossSectionArea: 0.0225 m2
Pset_ColumnCommon - LoadBearing: yes; FireRating: S/I; Status: NEW
Otros - Familia: Pilar; Familia y tipo: Pilar: 150x150 mm; ID de tipo: 587587; Tipo: 150x150 mm
Restricciones - Delimitación de habitación: yes; Estilo de pilar: Vertical; Se mueve con rejillas: yes
Datos - NDI: NDI-1
Datos de identidad - Tiene asociación: no
Materiales y acabados - Material estructural: Madera Oscura
Proceso por fases - Fase de creación: New Construction
Estructura - Recubrimiento de armadura - Cara inferior: Rebar Cover 1 <25 mm>; Recubrimiento de armadura - Cara superior: Rebar Cover 1 <25 mm>; Recubrimiento de armadura - Otras caras: Rebar Cover 1 <25 mm>
Name (Pilar:150x150 mm:...) | In | Length (cm) = Longitud (cm) | OuterSurfaceArea (m2) | GrossVolume (m3) = NetVolume (m3) = Volumen (m3) | Desfase de base (cm) | Desfase superior (cm) | Marca de ubicación de pilar | Nivel = Nivel base | Nivel superior
588034 | NOG_BASE PILARES | 661 | 3.966 | 0.148725 | 70 | -50 | D(14)-1(-14) | NOG_BASE PILARES | NOG_Pilares Cara Superior
588723 | NOG_BASE PILARES | 661 | 3.966 | 0.148725 | 70 | -50 | D(14)-4(14) | NOG_BASE PILARES | NOG_Pilares Cara Superior
588759 | NOG_BASE PILARES | 661 | 3.966 | 0.148725 | 70 | -50 | D(14)-3(11) | NOG_BASE PILARES | NOG_Pilares Cara Superior
588820 | NOG_BASE PILARES | 661 | 3.966 | 0.148725 | 70 | -50 | D(14)-2(-11) | NOG_BASE PILARES | NOG_Pilares Cara Superior
589291 | NOG_BASE PILARES | 661 | 3.966 | 0.148725 | 120 | 0 | A(-14)-1(-14) | NOG_BASE PILARES | NOG_Pilares Cara Superior
589292 | NOG_BASE PILARES | 661 | 3.966 | 0.148725 | 120 | 0 | A(-14)-4(14) | NOG_BASE PILARES | NOG_Pilares Cara Superior
589293 | NOG_BASE PILARES | 661 | 3.966 | 0.148725 | 120 | 0 | A(-14)-3(11) | NOG_BASE PILARES | NOG_Pilares Cara Superior
589294 | NOG_BASE PILARES | 661 | 3.966 | 0.148725 | 120 | 0 | A(-14)-2(-11) | NOG_BASE PILARES | NOG_Pilares Cara Superior
589796 | NOG_BASE PILARES | 663 | 3.978 | 0.149175 | 85 | -33 | C(11)-1(-14) | NOG_BASE PILARES | NOG_Pilares Cara Superior
589830 | NOG_BASE PILARES | 663 | 3.978 | 0.149175 | 85 | -33 | C(11)-4(14) | NOG_BASE PILARES | NOG_Pilares Cara Superior
589851 | NOG_BASE PILARES | 660 | 3.96 | 0.1485 | 105 | -16 | B(-11)-1(-14) | NOG_BASE PILARES | NOG_Pilares Cara Superior
589852 | NOG_BASE PILARES | 660 | 3.96 | 0.1485 | 105 | -16 | B(-11)-4(14) | NOG_BASE PILARES | NOG_Pilares Cara Superior
589918 | NOG_BASE PILARES | 195 | 1.17 | 0.043875 | 85 | 0 | C(11)-3(11) | NOG_BASE PILARES | NOG_PISO 1
589987 | NOG_BASE PILARES | 195 | 1.17 | 0.043875 | 85 | 0 | C(11)-2(-11) | NOG_BASE PILARES | NOG_PISO 1
590009 | NOG_BASE PILARES | 175 | 1.05 | 0.039375 | 105 | 0 | B(-11)-3(11) | NOG_BASE PILARES | NOG_PISO 1
590010 | NOG_BASE PILARES | 175 | 1.05 | 0.039375 | 105 | 0 | B(-11)-2(-11) | NOG_BASE PILARES | NOG_PISO 1
590835 | NPT | 464 | 2.784 | 0.1044 | -2 | -16 | B(-11)-2 | NPT | NOG_Pilares Cara Superior
590980 | NPT | 464 | 2.784 | 0.1044 | -2 | -16 | B(-11)-3 | NPT | NOG_Pilares Cara Superior
591002 | NPT | 447 | 2.682 | 0.100575 | -2 | -33 | C(11)-2 | NPT | NOG_Pilares Cara Superior
591003 | NPT | 447 | 2.682 | 0.100575 | -2 | -33 | C(11)-3 | NPT | NOG_Pilares Cara Superior

# IfcCovering: Techo compuesto:Cielo Placa Volcanita ST + Melamina, Techo compuesto:Cielo Placa Volcanita ST + Melamina:711880
In: NOG_PISO 1
Type - PredefinedType: CEILING
Type - Otros - Categoría: Techos; Nombre de familia: Techo compuesto
Type - Construcción - Grosor: 2.5 cm
Type - Gráficos - Color de relleno de detalle bajo: 0
Type - Datos de identidad - Descripción: Cielo: volcanita ST 10 mm + melamina 15 mm. Barrera de vapor de polietileno 0,2 mm continua tras la volcanita, con traslapes sellados.; Marca de tipo: CI1; Nombre de tipo: Cielo Placa Volcanita ST + Melamina; Nota clave: RSC
Type - Propiedades analíticas - Absortancia: 0.7; Aspereza: 3
Material: Volcanita ST 1 cm, Rev Melamina tipo madera 1.5 cm
Pset_CoveringCommon - IsExternal: no; FireRating: S/I; Status: NEW
BaseQuantities - GrossCeilingArea: 64.9549 m2
Otros - Familia: Techo compuesto; Familia y tipo: Techo compuesto: Cielo Placa Volcanita ST + Melamina; ID de tipo: 711801; Tipo: Cielo Placa Volcanita ST + Melamina
Restricciones - Delimitación de habitación: yes; Nivel: NOG_PISO 1; Desfase de altura desde nivel: 318.5 cm
Datos - NDI: NDI-1
Cotas - Área: 64.9549 m2; Perímetro: 6302.7 cm; Volumen: 1.62304 m3
Proceso por fases - Fase de creación: New Construction

# IfcCurtainWall: Muro cortina:Ventanas 1 Perfiles 100x35cm v2 (3)
In: NOG_PISO 1
Type - Otros - Categoría: Muros; Nombre de familia: Muro cortina
Type - Construcción - Condición de unión: Sin definir; Función: Exterior; Incrustar automáticamente: no; Panel de muro cortina: System Panel : Termopanel 2
Type - Datos de identidad - Descripción: Muro cortina interior. Vidrio DVH (termopanel) Low-E 24 mm con gas argon.; Marca de tipo: MC1; Nombre de tipo: Ventanas 1 Perfiles 100x35cm v2; Nota clave: MCI
Type - Rejilla horizontal - Ajustar para tamaño de montante: yes; Diseño: Ninguno; Espaciado: 150 cm
Type - Rejilla vertical - Ajustar para tamaño de montante: yes; Diseño: Número fijo; Espaciado: 150 cm
Type - Montantes horizontales - Tipo de borde 1: Montante rectangular : 70 x 100mm; Tipo de borde 2: Montante rectangular : 70 x 100mm
Type - Montantes verticales - Tipo de borde 1: Montante rectangular : 70 x 100mm; Tipo de borde 2: Montante rectangular : 70 x 100mm; Tipo de interior: Montante rectangular : 70 x 100mm
Pset_CurtainWallCommon - IsExternal: yes; FireRating: S/I; Status: NEW
BaseQuantities - Width: 2.5 cm; Height: 300 cm
Otros - Familia: Muro cortina; Familia y tipo: Muro cortina: Ventanas 1 Perfiles 100x35cm v2; ID de tipo: 591030; Tipo: Ventanas 1 Perfiles 100x35cm v2
Restricciones - Delimitación de habitación: yes; Relacionado con masa: no; Desfase superior: 0 cm; La base está enlazada: no; La parte superior está enlazada: no; Restricción de base: NOG_PISO 1; Altura desconectada: 300 cm; Desfase de base: 21 cm
Datos - NDI: NDI-1
Proceso por fases - Fase de creación: New Construction
Estructura - Estructura: no; Uso estructural: No portante
Rejilla horizontal - Ángulo: 0 deg; Desfase: 0 cm; Justificación: Inicio; Número: 4
Rejilla vertical - Ángulo: 0 deg; Desfase: 0 cm; Justificación: Inicio; Número: 2
Definición de sección transversal - Sección transversal: Vertical
Name (Muro cortina:Ventanas 1 Perfiles 100x35cm v2:...) | GrossSideArea (m2) = Área (m2) | Longitud (cm)
591578 | 9.0975 | 303.25
591797 | 9.195 | 306.5
637015 | 9 | 300

# IfcDistributionPort (14)
Description: Flow
Name | FlowDirection
OutPort_624003_1 | SOURCE
OutPort_625820_4 | SOURCE
OutPort_625820_5 | SOURCE
OutPort_625820_6 | SOURCE
InPort_625820_7 | SINK
OutPort_625820_8 | SOURCE
OutPort_626171_1 | SOURCE
OutPort_626173_4 | SOURCE
OutPort_626173_5 | SOURCE
OutPort_626173_6 | SOURCE
InPort_626173_7 | SINK
OutPort_626173_8 | SOURCE
InPort_669973_1 | SINK
InPort_669973_2 | SINK

# IfcDoor: TBC-P-PuertaSimpleMadera:TBC-ARQ-Puerta Simple Madera-P1-0.75x2.10 (2)
Type - ParameterTakesPrecedence: no; Sizeable: no; Material: TBC_PuertaMaderaMaciza
Type - Otros - Categoría: Puertas; Nombre de familia: TBC-P-PuertaSimpleMadera
Type - Construcción - Función: Interior; Cierre de muro: Por anfitrión
Type - Cotas - Altura: 194.5 cm; Altura bruta: 197 cm; Anchura: 80 cm; Anchura bruta: 85 cm; Grosor: 4.2 cm; Marco_Aleta: 1 cm; Marco_Espesor: 2.5 cm
Type - Datos de identidad - Comentarios de tipo: Puerta simple madera; Descripción: Puerta interior de bano 80x195 cm, hoja y marco de madera maciza.; Marca de tipo: P1; Nombre de tipo: TBC-ARQ-Puerta Simple Madera-P1-0.75x2.10; Nota clave: PBA; Número OmniClass: 23.30.10.00; Título OmniClass: Doors
Type - Materiales y acabados - Mat_Marco: TBC_PuertaMaderaMaciza; Mat_Panel: TBC_PuertaMaderaMaciza
Type - Propiedades analíticas - Definir propiedades térmicas por: Tipo esquemático; Construcción analítica: <Ninguno>
OverallHeight: 197 cm; OverallWidth: 85 cm
Pset_DoorCommon - IsExternal: no; FireRating: S/I; Status: NEW
BaseQuantities - Height: 194.5 cm; Width: 80 cm; Area: 1.556 m2
Otros - Familia: TBC-P-PuertaSimpleMadera; Familia y tipo: TBC-P-PuertaSimpleMadera: TBC-ARQ-Puerta Simple Madera-P1-0.75x2.10; ID de anfitrión: 624915; ID de tipo: 436699; Tipo: TBC-ARQ-Puerta Simple Madera-P1-0.75x2.10
Construcción - Marco_Offset: 6 cm
Datos - NDI: NDI-1
Cotas - Angulo Apertura 2D: 90 deg; Área: 2.28184 m2; Marco_Ancho: 7 cm; Volumen: 0.0759109 m3
Proceso por fases - Fase de creación: New Construction
Name (TBC-P-PuertaSimpleMadera:TBC-ARQ-Puerta Simple Madera-P1-0.75x2.10:...) | In | Altura de extremo inicial (cm) | Nivel | Altura de antepecho (cm) | Marca
625171 | NPT | 194.5 | NPT | 0 | 7
625263 | NOG_PISO 1 | 217.5 | NOG_PISO 1 | 23 | 8

# IfcDoor: TBC-P-PuertaSimpleMadera:TBC_ARQ_PuertaSimple_P85, TBC-P-PuertaSimpleMadera:TBC_ARQ_PuertaSimple_P85:603907
In: NPT
Type - ParameterTakesPrecedence: no; Sizeable: no; Material: TBC_PuertaMetalicaPintada
Type - Otros - Categoría: Puertas; Nombre de familia: TBC-P-PuertaSimpleMadera
Type - Construcción - Función: Interior; Cierre de muro: Por anfitrión
Type - Cotas - Altura: 195.5 cm; Altura bruta: 198 cm; Anchura: 80 cm; Anchura bruta: 85 cm; Grosor: 4.2 cm; Marco_Aleta: 1 cm; Marco_Espesor: 2.5 cm
Type - Datos de identidad - Descripción: Puerta de acceso 80x196 cm, metalica: hoja MDF con chapa galvanizada y pintura epoxica; marco metalico pintado.; Marca de tipo: P2; Nombre de tipo: TBC_ARQ_PuertaSimple_P85; Nota clave: PAC; Número OmniClass: 23.30.10.00; Título OmniClass: Doors
Type - Materiales y acabados - Mat_Marco: TBC_PuertaMetalicaPintada; Mat_Panel: TBC_PuertaMetalicaPintada
Type - Propiedades analíticas - Definir propiedades térmicas por: Tipo esquemático; Construcción analítica: <Ninguno>
OverallHeight: 198 cm; OverallWidth: 85 cm
Pset_DoorCommon - IsExternal: yes; FireRating: S/I; Status: NEW
BaseQuantities - Height: 195.5 cm; Width: 80 cm; Area: 1.564 m2
Otros - ID de anfitrión: 590689; Altura de extremo inicial: 195.5 cm; Familia: TBC-P-PuertaSimpleMadera; Familia y tipo: TBC-P-PuertaSimpleMadera: TBC_ARQ_PuertaSimple_P85; ID de tipo: 436705; Tipo: TBC_ARQ_PuertaSimple_P85
Restricciones - Nivel: NPT; Altura de antepecho: 0 cm
Construcción - Marco_Offset: 6 cm
Datos - NDI: NDI-1
Cotas - Angulo Apertura 2D: 90 deg; Área: 2.29236 m2; Marco_Ancho: 7 cm; Volumen: 0.0762875 m3
Datos de identidad - Marca: 6
Proceso por fases - Fase de creación: New Construction

# IfcFlowTerminal: Inodoro-Cadiz-16032026:INODORO CÁDIZ_CODO CONEXION 25 CM (2)
Type - Material: EMPAQUE, PVC, INODORO, METAL CROMADO
Type - Otros - Categoría: Aparatos sanitarios; CODO CONEXION 20.5 CM: no; CODO CONEXION 25 CM: yes; CODO CONEXION 30.5 CM: no; Nombre de familia: Inodoro-Cadiz-16032026; shaft: no; TUBO CONEXION A MURO: no
Type - Restricciones - Elevación por defecto: 0 cm
Type - Cotas - H_TOTAL: 77.5 cm; RETIRO A PARED: 1.5 cm; SALIDA Ø: 18.5 cm
Type - Datos de identidad - Descripción: Inodoro Fanaloza Cadiz multidescarga 4,1/6 L, dos piezas, asiento cierre suave. SKU JS6470571301CF. Certificado CESMEC NCh 407.; F_Alto: 77.5 cm; F_Ancho: 36.5 cm; F_Certificación: Producto certificado por CESMEC en base al cumplimiento de la Norma Chilena NCh 407 2012 para Artefactos Sanitarios de loza vítrea, según modelo de certificación ISO CASCO 1; F_Color: Blanco; F_Consumo / Capacidad de agua (L): 4.1 / 6 L; F_Contacto comercial: ventas@fanaloza.cl; F_Descripción: Inodoro de dos piezas multidescarga con descarga dual de 4,1/6 L, trampa cubierta. Con asiento cierre suave; F_Distancia de instalación a muro terminado (cm): a muro/ 20,5/ 25 /30,5 con conectores; F_Peso: 0.359904 kN; F_Productos incluidos: Asiento, Fitting, pernos de anclaje en L; F_Productos necesarios para instalación: Flexible 1/2" x 15/16" Hi-HI 30 cm, Llave Angular 1/2"x 1/2" HE-HE, codo conector; F_Profundidad: 69.5 cm; F_SKU: JS6470571301CF; F_Tipo de aro: Especial; F_Tipo de instalación: Multidescarga; F_Tolerancia dimensional: <20 cm:+- 3%, >20 cm: 0,6 cm máx.; Marca de tipo: SN2; Nombre de tipo: INODORO CÁDIZ_CODO CONEXION 25 CM; Nota clave: SN2; Número OmniClass: 23.45.00.00; Título OmniClass: Sanitary, Laundry, and Cleaning Equipment; URL: https://www.fanaloza.cl/producto/inodoro-cadiz-multidescarga/
Pset_LightFixtureTypeCommon - Status: NEW; sets with these values: 2
Otros - Familia: Inodoro-Cadiz-16032026; Familia y tipo: Inodoro-Cadiz-16032026: INODORO CÁDIZ_CODO CONEXION 25 CM; ID de anfitrión: 625051; ID de tipo: 620158; Tipo: INODORO CÁDIZ_CODO CONEXION 25 CM
Restricciones - Nivel: NOG_PISO 1; Elevación desde el nivel: 23 cm
Datos - NDI: NDI-1
Cotas - Área: 1.70643 m2; Volumen: 0.0584002 m3
Mecánica - Clasificación de sistema: Sanitario,Agua fría sanitaria,Sanitario
Proceso por fases - Fase de creación: New Construction
Name (Inodoro-Cadiz-16032026:INODORO CÁDIZ_CODO CONEXION 25 CM:...) | In
625820 | 2
626173 | 3

# IfcFlowTerminal: KRZ 040A 40SD00 24 4K0 2X V.2 FLP:Standart (12)
Type - Material: Aluminium, PC/ABS Plastic
Type - Otros - Categoría: Luminarias; Nombre de familia: KRZ 040A 40SD00 24 4K0 2X V.2 FLP
Type - Restricciones - Elevación por defecto: 0.131234 cm
Type - Cotas - Height: 12.2 cm; Length: 15.5 cm; Width: 28.5 cm
Type - Electricidad - Lámpara: COB LED
Type - Eléctrico - Iluminación - Diffuser: 24° Reflector
Type - Eléctrico - Cargas - Power Consumption: 40 W
Type - General - Installation: Recessed mounted; IP Grade: IP20; Order Code: 3236292; Product Code: KRZ 040A 40SD00 24 4K2 2X V.2 FLP
Type - Datos de identidad - Fabricante: EAE; Modelo: KRIZA; Nombre de tipo: Standart; URL: https://eaelighting.com/en/product/kriza-p1701
Type - Fotometría - Correlated Color Temp.: 4000 K; CRI: >80; Efficacy: 107.14 s3*lm/kg/m2; Final Luminious Flux: 4286 lm
Type - Materiales y acabados - Housing: Aluminium
Pset_LightFixtureTypeCommon - Status: NEW; sets with these values: 2
Otros - Familia: KRZ 040A 40SD00 24 4K0 2X V.2 FLP; Familia y tipo: KRZ 040A 40SD00 24 4K0 2X V.2 FLP: Standart; ID de tipo: 743594; Tipo: Standart
Restricciones - Anfitrión: Techo compuesto : Cielo Placa Volcanita ST + Melamina
Datos - NDI: NDI-1
Cotas - Área: 0.106909 m2; Volumen: 0.00112972 m3
Eléctrico - Iluminación - Calcular coeficiente de utilización: no
Proceso por fases - Fase de creación: New Construction
Name (KRZ 040A 40SD00 24 4K0 2X V.2 FLP:Standart:...) | In | Elevación desde el nivel (cm)
743643 | 4 | 318.5 | Restricciones - Nivel: NOG_PISO 1; Nivel de tabla de planificación: NOG_PISO 1
743923 | 4 | 0
744023 | 1 | 0
744234 | 1 | 0
744516 | 1 | 0
744553 | 1 | 0
744684 | 2 | 318.5 | Restricciones - Nivel: NOG_PISO 1; Nivel de tabla de planificación: NOG_PISO 1
744863 | 3 | 0
744996 | 1 | 0
744998 | 1 | 0
744999 | 1 | 0
745000 | 1 | 0

# IfcFlowTerminal: Kitchen_Taps-Mixers_hansgrohe_72806000-Talis-M54-Single-lever-kitchen:Chrome 000, Kitchen_Taps-Mixers_hansgrohe_72806000-Talis-M54-Single-lever-kitchen:Chrome 000:669973
In: 4
Type - Material: 72806000 Talis M54 Single lever kitchen mixer U 220, 1jet - 72806000 - Chrome
Type - Otros - Categoría: Aparatos sanitarios; BOS_0_Material: 72806000 Talis M54 Single lever kitchen mixer U 220, 1jet - 72806000 - Chrome; BOS_0_Visibility: yes; BOS_1_Material: 72806000 Talis M54 Single lever kitchen mixer U 220, 1jet - 72806000 - Chrome; BOS_1_Visibility: yes; BOS_10_Material: 72806000 Talis M54 Single lever kitchen mixer U 220, 1jet - 72806000 - Chrome; BOS_10_Visibility: yes; BOS_11_Material: 72806000 Talis M54 Single lever kitchen mixer U 220, 1jet - 72806000 - Chrome; BOS_11_Visibility: yes; BOS_12_Material: 72806000 Talis M54 Single lever kitchen mixer U 220, 1jet - 72806000 - Chrome; BOS_12_Visibility: yes; BOS_13_Material: 72806000 Talis M54 Single lever kitchen mixer U 220, 1jet - 72806000 - Chrome; BOS_13_Visibility: yes; BOS_14_Material: 72806000 Talis M54 Single lever kitchen mixer U 220, 1jet - 72806000 - Chrome; BOS_14_Visibility: yes; BOS_15_Material: 72806000 Talis M54 Single lever kitchen mixer U 220, 1jet - 72806000 - Chrome; BOS_15_Visibility: yes; BOS_16_Material: 72806000 Talis M54 Single lever kitchen mixer U 220, 1jet - 72806000 - Chrome; BOS_16_Visibility: yes; BOS_17_Visibility: yes; BOS_18_Visibility: yes; BOS_19_Visibility: yes; BOS_2_Material: 72806000 Talis M54 Single lever kitchen mixer U 220, 1jet - 72806000 - Chrome; BOS_2_Visibility: yes; BOS_20_Visibility: yes; BOS_21_Visibility: yes; BOS_22_Visibility: yes; BOS_23_Visibility: yes; BOS_3_Material: 72806000 Talis M54 Single lever kitchen mixer U 220, 1jet - 72806000 - Chrome; BOS_3_Visibility: yes; BOS_4_Material: 72806000 Talis M54 Single lever kitchen mixer U 220, 1jet - 72806000 - Chrome; BOS_4_Visibility: yes; BOS_5_Material: 72806000 Talis M54 Single lever kitchen mixer U 220, 1jet - 72806000 - Chrome; BOS_5_Visibility: yes; BOS_6_Material: 72806000 Talis M54 Single lever kitchen mixer U 220, 1jet - 72806000 - Chrome; BOS_6_Visibility: yes; BOS_7_Material: 72806000 Talis M54 Single lever kitchen mixer U 220, 1jet - 72806000 - Chrome; BOS_7_Visibility: yes; BOS_8_Material: 72806000 Talis M54 Single lever kitchen mixer U 220, 1jet - 72806000 - Chrome; BOS_8_Visibility: yes; BOS_9_Material: 72806000 Talis M54 Single lever kitchen mixer U 220, 1jet - 72806000 - Chrome; BOS_9_Visibility: yes; Nombre de familia: Kitchen_Taps-Mixers_hansgrohe_72806000-Talis-M54-Single-lever-kitchen
Type - Restricciones - Elevación por defecto: 0 cm
Type - General - Edition number: 1; Brand url: http://www.hansgrohe-int.com; Design country: Germany; Manufacturer country: Germany; Manufacturer name: hansgrohe; Product family: Talis M54; Product group: Kitchen mixers; Product name: 72806000 Talis M54 Single lever kitchen mixer U 220, 1jet; Product SKU: 72806000; QR code: http://bimobject.com/hansgrohe/product/72806000; Region Africa: All; Region Antarctica: All; Region Asia: All; Region Europe: All; Region Middle East: All; Region North America: All; Region Oceania: All; Region South America: All
Type - Datos de identidad - Descripción: Griferia monomando de cocina Hansgrohe Talis M54, ref. 72806000, cromo.; GTIN code: https://4059625255308; Installation instructions: https://www.hansgrohe.com/articledetail--72806000; Marca de tipo: SN3; Nombre de tipo: Chrome 000; Nota clave: SN3; Número OmniClass: 23.45.00.00; Product data url: https://bimobject.com/hansgrohe/product/72806000; Product url: https://www.hansgrohe.com/articledetail--72806000; Technical description: https://www.hansgrohe.com/articledetail--72806000; Título OmniClass: Sanitary, Laundry, and Cleaning Equipment
Type - Materiales y acabados - Material main: Chrome
Pset_LightFixtureTypeCommon - Status: NEW; sets with these values: 2
Otros - Familia: Kitchen_Taps-Mixers_hansgrohe_72806000-Talis-M54-Single-lever-kitchen; Familia y tipo: Kitchen_Taps-Mixers_hansgrohe_72806000-Talis-M54-Single-lever-kitchen: Chrome 000; ID de tipo: 670162; Tipo: Chrome 000
Restricciones - Nivel: NOG_PISO 1; Anfitrión: Suelo : SIP e=210mm; Desfase desde el anfitrión: 91.9975 cm; Elevación desde el nivel: 112.997 cm
Datos - NDI: NDI-1
Cotas - Área: 0.0455776 m2; Volumen: 0.000543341 m3
Datos de identidad - Marca: 8
Mecánica - Clasificación de sistema: Agua caliente sanitaria,Agua fría sanitaria
Proceso por fases - Fase de creación: New Construction

# IfcFlowTerminal: Sanitary_Compound-Units_Roca_851974XXX-The-Gap-Pack-base-unit-with-tw:547 - Matt grey (2)
Type - Material: Roca - THE GAP - 547 Matt grey, Roca - THE GAP - White, Roca - THE GAP - Black, Roca - THE GAP - Chrome, Roca - THE GAP - Mirror, Roca - THE GAP - LED
Type - Otros - Categoría: Aparatos sanitarios; Nombre de familia: Sanitary_Compound-Units_Roca_851974XXX-The-Gap-Pack-base-unit-with-tw; z_HL: Accessories : A816761001 - Hooks (left); z_HR: Accessories : A816761001 - Hooks (right); z_LC: Legs : A816827339 - Optional 2-leg set - Cool grey; z_LW: Legs : A816827458 - Optional 2-leg set - Warm grey; z_TL: Accessories : A816760001 - Towel rail (left); z_TR: Accessories : A816760001 - Towel rail (right)
Type - Restricciones - Elevación por defecto: 0 cm
Type - Datos - Connector Description: Drain
Type - Cotas - Depth: 60 cm; Diameter: 3.18 cm; Height: 57.5 cm; Width: 46 cm
Type - General - Product name: 851974XXX The Gap Pack (base unit with two drawers for centred over countertop basin and Eidos LED mirror); Product SKU: 851974XXX; QR code: https://bimobject.com/roca/product/851974xxx
Type - Datos de identidad - Descripción: Pack (base unit with two drawers for centred over countertop basin and Eidos LED mirror). Designed by Antonio Bullo, this collection delivers both a compact and functional style. Its wide range enables one to optimise any bathroom space. Its modern and stylish lines make of it an intelligent choice.; Fabricante: Roca; Marca de tipo: SN1; Modelo: 851974XXX The Gap Pack (base unit with two drawers for centred over countertop basin and Eidos LED mirror); Nombre de tipo: 547 - Matt grey; Nota clave: SN1; Número OmniClass: 23.21.19.15.33.13; Product data url: https://bimobject.com/roca/product/851974xxx; Product url: https://www.export.roca.com/search?q=851974...; Technical description: https://www.export.roca.com/roca-services/productSheet30/EX/en/A851963402/; URL: http://www.roca.com/; Youtube clip: https://www.youtube.com/watch?v=68jtjk-3_i12
Type - Materiales y acabados - Details material: Roca - THE GAP - Chrome; Handle material: Roca - THE GAP - Black; LED material: Roca - THE GAP - LED; Main material: Roca - THE GAP - 547 Matt grey; Main material 90: Roca - THE GAP - 547 Matt grey; Material main: Chipboard; Material secondary: Vitreous china; Mirror material: Roca - THE GAP - Mirror; Secondary material: Roca - THE GAP - White
Material: Roca - THE GAP - Chrome, Roca - THE GAP - 547 Matt grey, Roca - THE GAP - Black, Roca - THE GAP - White
Pset_LightFixtureTypeCommon - Status: NEW; sets with these values: 2
Otros - Familia: Sanitary_Compound-Units_Roca_851974XXX-The-Gap-Pack-base-unit-with-tw; Familia y tipo: Sanitary_Compound-Units_Roca_851974XXX-The-Gap-Pack-base-unit-with-tw: 547 - Matt grey; ID de tipo: 623975; Tipo: 547 - Matt grey
Restricciones - Nivel: NOG_PISO 1; Accessories: Accessories : No; Anfitrión: Suelo : SIP e=210mm; Desfase desde el anfitrión: 2 cm; Elevación desde el nivel: 23 cm; Legs: Legs : No
Datos - NDI: NDI-1
Cotas - Área: 1.34301 m2; Volumen: 0.153274 m3
Mecánica - Clasificación de sistema: Sanitario
Proceso por fases - Fase de creación: New Construction
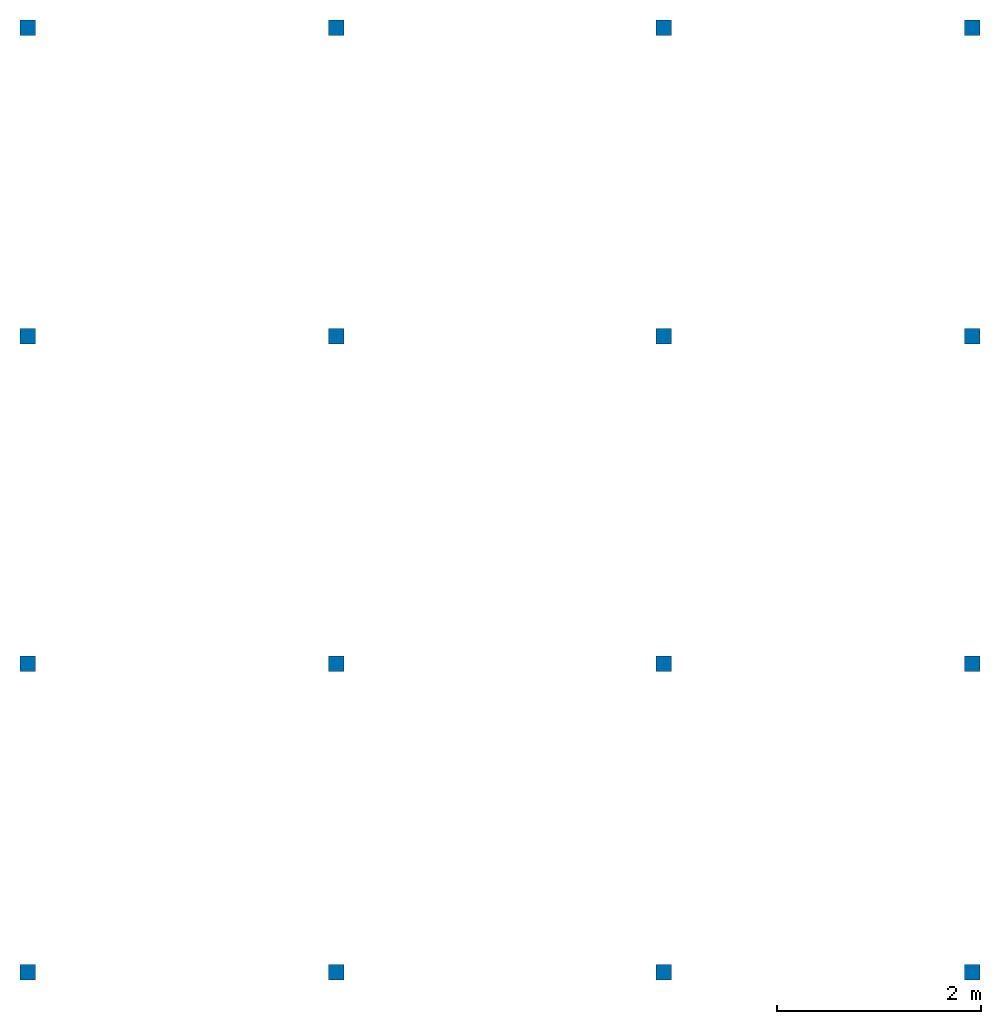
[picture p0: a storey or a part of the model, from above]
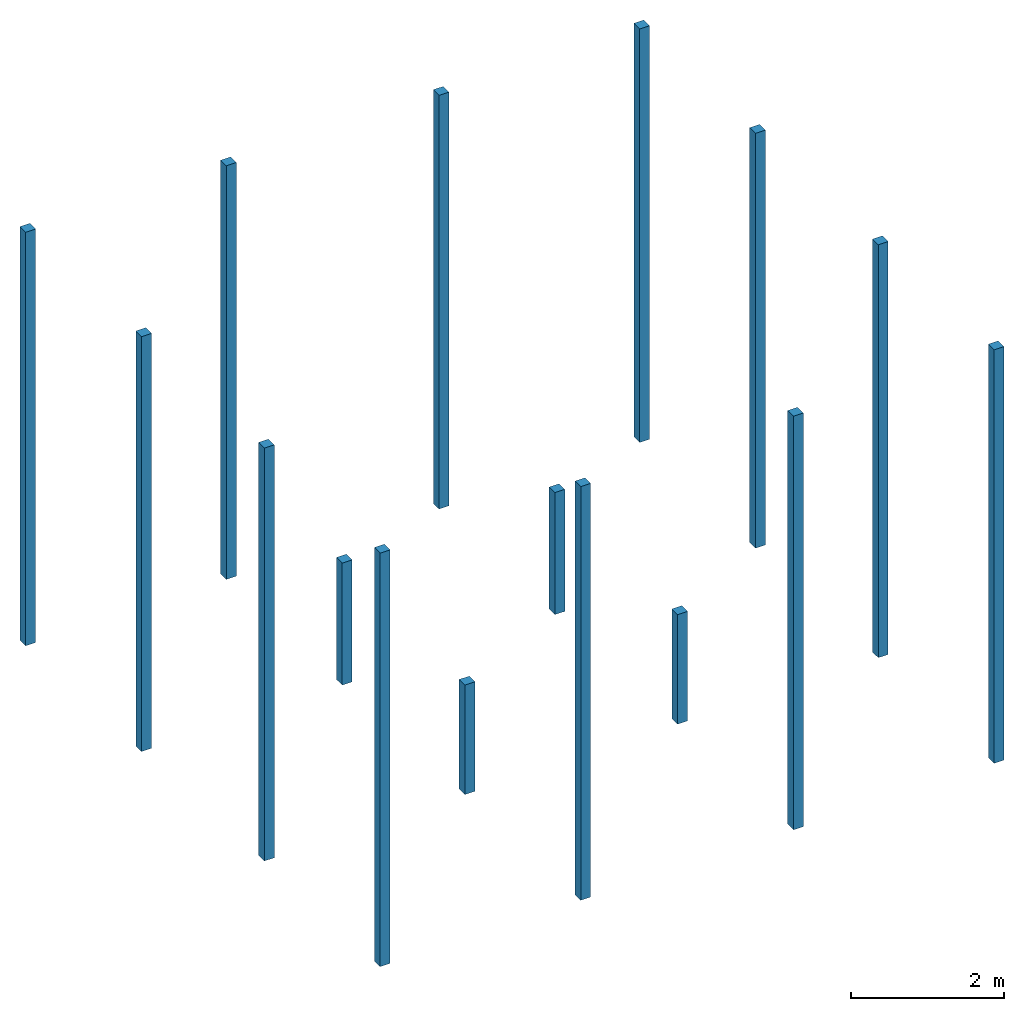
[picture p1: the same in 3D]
Properties of the parts of a building model (IFC2X3), part 2 of 2

# IfcFlowTerminal: Sanitary_Compound-Units_Roca_851974XXX-The-Gap-Pack-base-unit-with-tw:547 - Matt grey (2)
Visibilidad - A816760001 - Towel rail (left): no; A816760001 - Towel rail (right): no; A816761001 - Hooks (left): no; A816761001 - Hooks (right): no; A816826458 - Optional 2-leg set - Warm grey: no; A816827339 - Optional 2-leg set - Cool grey: no
Name (Sanitary_Compound-Units_Roca_851974XXX-The-Gap-Pack-base-unit-with-tw:547 - Matt grey:...) | In
624003 | 2
626171 | 3

# IfcFlowTerminal: s719_u765_under_mount_sink_370_370_43430800:Stainless Steel, s719_u765_under_mount_sink_370_370_43430800:Stainless Steel:669974
In: 4
Type - Material: 3613c15e_7b91_4216_8e6b_cbbc72836491
Type - Otros - Categoría: Aparatos sanitarios; BOS_0_127_127_127_Visibility: no; BOS_0_Native_Visibility: yes; BOS_0_Visibility: 1; BOS_1_127_127_127_Visibility: no; BOS_1_Native_Visibility: yes; BOS_1_Visibility: 1; BOS_2_127_127_127_Visibility: no; BOS_2_Native_Visibility: yes; BOS_2_Visibility: 1; BOSUseNativeGeometries: 1; BOS_0_Blue: 127; BOS_0_Green: 127; BOS_0_Material: 0868dbe1_63e3_42af_8e82_4d183f3736bf; BOS_0_Red: 127; BOS_1_Blue: 127; BOS_1_Green: 127; BOS_1_Material: 0868dbe1_63e3_42af_8e82_4d183f3736bf; BOS_1_Red: 127; BOS_2_Blue: 127; BOS_2_Green: 127; BOS_2_Material: 3613c15e_7b91_4216_8e6b_cbbc72836491; BOS_2_Red: 127; Nombre de familia: s719_u765_under_mount_sink_370_370_43430800
Type - Restricciones - Elevación por defecto: 0.131234 cm
Type - General - Edition number: 1; Brand url: http://www.hansgrohe-int.com; Design country: Germany; Manufacturer country: Germany; Manufacturer name: hansgrohe; Nominal height: 0; Nominal width: 0; Product family: S71; Product group: Sinks; Product name: S719-U765 under-mount sink 370/370 43430800; Product SKU: 43430800; QR code: http://bimobject.com/hansgrohe/product/43430800; Region Africa: AO, BF, BI, BJ, BW, CD, CF, CG, CI, CM, CV, DJ, DZ, EH, ER, ET, GA, GH, GM, GN, GQ, GW, KE, KM, LR, LS, LY, MA, MG, ML, MR, MU, MW, MZ, NA, NE, NG, RE, RW, SC, SD, SH, SL, SN, SO, SS, ST, SZ, TD, TG, TN, TZ, UG, YT, ZA, ZM, ZW; Region Asia: AM, AZ, BD, BN, BT, CC, CN, CX, GE, HK, ID, IN, IO, JP, KG, KH, KP, KR, KZ, LA, LK, MM, MN, MO, MV, MY, NP, PH, PK, SG, TH, TJ, TM, TW, UZ, VN; Region Europe: AD, AL, AT, AX, BA, BE, BG, BY, CH, CY, CZ, DE, DK, EE, ES, FI, FO, FR, GB, GG, GI, GR, HR, HU, IE, IM, IS, IT, JE, LI, LT, LU, LV, MC, MD, ME, MK, MT, NL, NO, PL, PT, RO, RS, RU, SE, SI, SJ, SK, SM, UA, VA; Region Middle East: AE, AF, BH, EG, IL, IQ, IR, JO, KW, LB, OM, PS, QA, SA, SY, TR, YE; Region North America: AG, AI, AW, BB, BL, BM, BQ, BS, BZ, CA, CR, CU, CW, DM, DO, GD, GL, GP, GT, HN, HT, JM, KN, KY, LC, MF, MQ, MS, MX, NI, PA, PM, PR, SV, SX, TC, TT, US, VC, VG, VI; Region Oceania: AS, AU, CK, FJ, FM, GU, KI, MH, MP, NC, NF, NR, NU, NZ, PF, PG, PN, PW, SB, TK, TL, TO, TV, UM, WF, WS, VU; Region South America: AR, BO, BR, CL, CO, EC, FK, GF, GY, PE, PY, SR, UY, VE; Weight Net (Kg): 0
Type - Datos de identidad - Descripción: Lavaplatos bajo cubierta de acero inoxidable.; EAN code: https://4059625007235; Installation instructions: https://pro.hansgrohe-int.com/suche.htm?searchtext=43430800; Marca de tipo: SN4; Nombre de tipo: Stainless Steel; Nota clave: SN4; Product data url: https://bimobject.com/hansgrohe/product/43430800; Product url: https://pro.hansgrohe-int.com/suche.htm?searchtext=43430800; Technical description: https://pro.hansgrohe-int.com/suche.htm?searchtext=43430800
Type - Materiales y acabados - Material main: Stainless steel
Pset_LightFixtureTypeCommon - Status: NEW; sets with these values: 2
Otros - Familia: s719_u765_under_mount_sink_370_370_43430800; Familia y tipo: s719_u765_under_mount_sink_370_370_43430800: Stainless Steel; ID de tipo: 670159; Tipo: Stainless Steel
Restricciones - Elevación desde el nivel: 0 cm; Desfase desde el anfitrión: 20.9975 cm; Plano de trabajo: <no asociado>
Datos - NDI: NDI-1
Cotas - Área: 0.614211 m2; Volumen: 0.0716986 m3
Proceso por fases - Fase de creación: New Construction

# IfcFooting: Footing-Rectangular:80X40X40cm (16)
In: NOG_PISO 1
Type - Material: Concrete, Cast-in-Place gray
Type - Otros - Categoría: Cimentación estructural; Nombre de familia: Footing-Rectangular
Type - Cotas - Anchura: 40 cm; Grosor de cimentación: 80 cm; Longitud: 40 cm
Type - Datos de identidad - Código de montaje: A1010100; Descripción: Zapata rectangular de hormigon armado 80x40x40 cm. Grado y enfierradura a confirmar por ingeniero calculista.; Descripción de montaje: Footings & Pile Caps; Marca de tipo: F2; Nombre de tipo: 80X40X40cm; Nota clave: ZAR; Número OmniClass: 23.25.05.17; Título OmniClass: Shallow Foundations
Classification: A1010100 Footings & Pile Caps (Uniformat)
Pset_FootingCommon - LoadBearing: yes; Status: NEW
Otros - Familia: Footing-Rectangular; Familia y tipo: Footing-Rectangular: 80X40X40cm; ID de tipo: 708929; Tipo: 80X40X40cm
Restricciones - Nivel: NOG_PISO 1; Se mueve con rejillas: yes; Anfitrión: Nivel : NOG_PISO 1
Datos - NDI: NDI-1
Cotas - Área: 0.16 m2; Volumen: 0.128 m3
Datos de identidad - Tiene asociación: no
Materiales y acabados - Material estructural: Concrete, Cast-in-Place gray
Proceso por fases - Fase de creación: New Construction
Estructura - Recubrimiento de armadura - Cara superior: Revestimiento de armadura 1 <25 mm>; Recubrimiento de armadura - Otras caras: Revestimiento de armadura 1 <25 mm>
Name (Footing-Rectangular:80X40X40cm:...) | Desfase de altura desde nivel (cm) | Elevación en parte inferior (cm) = Elevación en parte inferior de punto de reconocimiento (cm) | Elevación en parte superior (cm) = Elevación en parte superior de punto de reconocimiento (cm)
708924 | -160 | -140 | -60 | Datos de identidad - Marca: FUND
709496 | -175 | -155 | -75
709601 | -195 | -175 | -95
709615 | -210 | -190 | -110 | Estructura - Recubrimiento de armadura - Cara inferior: Rebar Cover 1 <25 mm>
709736 | -160 | -140 | -60
709738 | -175 | -155 | -75
709740 | -195 | -175 | -95
709742 | -210 | -190 | -110 | Estructura - Recubrimiento de armadura - Cara inferior: Rebar Cover 1 <25 mm>
709752 | -160 | -140 | -60
709754 | -175 | -155 | -75
709756 | -195 | -175 | -95
709758 | -210 | -190 | -110 | Estructura - Recubrimiento de armadura - Cara inferior: Rebar Cover 1 <25 mm>
709766 | -160 | -140 | -60
709768 | -175 | -155 | -75
709770 | -195 | -175 | -95
709772 | -210 | -190 | -110 | Estructura - Recubrimiento de armadura - Cara inferior: Rebar Cover 1 <25 mm>

# IfcFooting: Pile Cap:TBC-ARQ-Zapata aislada HA 75x75x45cm (16)
In: NTN
Type - Material: Concrete, Cast-in-Place gray
Type - Otros - Categoría: Cimentación estructural; Area of Mesh: 0.5625; Dummy: 1 m3; Dummy Area: 1 m2; Mesh Area: 0.5625 m2; Nombre de familia: Pile Cap; V: 1.125 m3; Volume: 1.125
Type - Cotas - Anchura: 75 cm; Grosor de cimentación: 45 cm; Longitud: 75 cm
Type - Datos de identidad - Código de montaje: A1010130; Comentarios de tipo: Fundacion aislada HA 75x75x45 cm; Descripción: Zapata aislada de hormigon armado 75x75x45 cm. Grado de hormigon y enfierradura a confirmar por ingeniero calculista.; Descripción de montaje: Pile Caps; Marca de tipo: F1; Nombre de tipo: TBC-ARQ-Zapata aislada HA 75x75x45cm; Nota clave: ZAP
Type - Texto - Pile Cap Type: PC1
PredefinedType: PAD_FOOTING; Classification: A1010130 Pile Caps (Uniformat)
Pset_FootingCommon - LoadBearing: yes; Status: NEW
Otros - Familia: Pile Cap; Familia y tipo: Pile Cap: TBC-ARQ-Zapata aislada HA 75x75x45cm; ID de tipo: 549564; Tipo: TBC-ARQ-Zapata aislada HA 75x75x45cm
Restricciones - Se mueve con rejillas: yes; Nivel: NTN; Anfitrión: Nivel : NTN; Desfase de altura desde nivel: -140 cm
Datos - NDI: NDI-1
Cotas - Elevación en parte inferior: -185 cm; Elevación en parte inferior de punto de reconocimiento: -185 cm; Elevación en parte superior: -140 cm; Elevación en parte superior de punto de reconocimiento: -140 cm
Datos de identidad - Tiene asociación: no
Materiales y acabados - Material estructural: Concrete, Cast-in-Place gray
Proceso por fases - Fase de creación: New Construction
Estructura - Recubrimiento de armadura - Cara inferior: Rebar Cover 1 <25 mm>; Recubrimiento de armadura - Cara superior: Revestimiento de armadura 1 <25 mm>; Recubrimiento de armadura - Otras caras: Revestimiento de armadura 1 <25 mm>
Texto - Concrete Cover: 40; Link Centres: 0; Mesh: A252; Reinforcement Grade: 460N/mm²
Name (Pile Cap:TBC-ARQ-Zapata aislada HA 75x75x45cm:...) | Área (m2) | Volumen (m3)
709377 | 0.5625 | 0.253125
709497 | 0.5625 | 0.229125
709602 | 0.5625 | 0.197125
709616 | 0.4025 | 0.181125
709737 | 0.5625 | 0.253125
709739 | 0.5625 | 0.229125
709741 | 0.5625 | 0.197125
709743 | 0.4025 | 0.181125
709753 | 0.5625 | 0.253125
709755 | 0.5625 | 0.229125
709757 | 0.5625 | 0.197125
709759 | 0.4025 | 0.181125
709767 | 0.5625 | 0.253125
709769 | 0.5625 | 0.229125
709771 | 0.5625 | 0.197125
709773 | 0.4025 | 0.181125

# IfcFurnishingElement: GDV_FAM_M04c_Aereo doble logia:GDV_FAM_M04c_Aereo doble logia (2)
Type - Material: Melamina Puertas Mueble de Cocina, Melamina Muebles Cocina
Type - Otros - Categoría: Mobiliario; Nombre de familia: GDV_FAM_M04c_Aereo doble logia
Type - Restricciones - Elevación por defecto: 0 cm
Type - Datos de identidad - Descripción: Mueble aereo doble, melamina.; Marca de tipo: MB4; Nombre de tipo: GDV_FAM_M04c_Aereo doble logia; Nota clave: MB4; Número OmniClass: 23.40.20.00; Título OmniClass: General Furniture and Specialties
Type - Materiales y acabados - Caras vistas: Melamina Puertas Mueble de Cocina; Interiores: Melamina Muebles Cocina
Pset_FurnitureTypeCommon - Status: NEW
Otros - Familia: GDV_FAM_M04c_Aereo doble logia; Familia y tipo: GDV_FAM_M04c_Aereo doble logia: GDV_FAM_M04c_Aereo doble logia; ID de tipo: 675019; Tipo: GDV_FAM_M04c_Aereo doble logia
Restricciones - Nivel: NOG_PISO 1; Se mueve con elementos cercanos: no; Elevación desde el nivel: 183 cm
Datos - NDI: NDI-1
Cotas - Alto módulo: 65 cm; Ancho módulo: 120 cm; Área: 3.14355 m2; Espesor módulo base: 1.5 cm; Espesor puerta: 1.8 cm; Profundidad módulo: 35 cm; Volumen: 0.0469935 m3
Proceso por fases - Fase de creación: New Construction
Name (GDV_FAM_M04c_Aereo doble logia:GDV_FAM_M04c_Aereo doble logia:...) | In | Anfitrión | Desfase desde el anfitrión (cm)
674965 | 4 | Suelo : SIP e=210mm | 162
677163 | NOG_PISO 1 | Suelo : Cubierta Cocina | 70

# IfcFurnishingElement: GDV_FAM_M04c_Aereo logia:GDV_FAM_M04c_Aereo logia (2)
In: NOG_PISO 1
Type - Material: Melamina Muebles Cocina, Melamina Puertas Mueble de Cocina
Type - Otros - Categoría: Mobiliario; Nombre de familia: GDV_FAM_M04c_Aereo logia
Type - Restricciones - Elevación por defecto: 0 cm
Type - Datos de identidad - Descripción: Mueble aereo simple, melamina.; Marca de tipo: MB5; Nombre de tipo: GDV_FAM_M04c_Aereo logia; Nota clave: MB5; Número OmniClass: 23.40.20.00; Título OmniClass: General Furniture and Specialties
Type - Materiales y acabados - Caras vistas: Melamina Puertas Mueble de Cocina; Interiores: Melamina Muebles Cocina
Pset_FurnitureTypeCommon - Status: NEW
Otros - Familia: GDV_FAM_M04c_Aereo logia; Familia y tipo: GDV_FAM_M04c_Aereo logia: GDV_FAM_M04c_Aereo logia; ID de tipo: 675017; Tipo: GDV_FAM_M04c_Aereo logia
Restricciones - Nivel: NOG_PISO 1; Se mueve con elementos cercanos: no; Elevación desde el nivel: 183 cm
Datos - NDI: NDI-1
Cotas - Alto módulo: 65 cm; Ancho módulo: 30 cm; Área: 1.10481 m2; Espesor módulo base: 1.8 cm; Espesor puerta: 1.8 cm; Profundidad módulo: 35 cm; Volumen: 0.0181282 m3
Proceso por fases - Fase de creación: New Construction
Name (GDV_FAM_M04c_Aereo logia:GDV_FAM_M04c_Aereo logia:...) | Anfitrión | Desfase desde el anfitrión (cm)
677211 | Suelo : SIP e=210mm | 162
677515 | Suelo : Cubierta Cocina | 70

# IfcFurnishingElement: GDV_FAM_M05e_Lavaplatos:GDV_FAM_M05e_Lavaplatos, GDV_FAM_M05e_Lavaplatos:GDV_FAM_M05e_Lavaplatos:673346
In: 4
Type - Material: Melamina Puertas Mueble de Cocina, <Unnamed>
Type - Otros - Categoría: Mobiliario; Nombre de familia: GDV_FAM_M05e_Lavaplatos
Type - Restricciones - Elevación por defecto: 0 cm
Type - Datos de identidad - Descripción: Mueble lavaplatos, melamina.; Marca de tipo: MB3; Nombre de tipo: GDV_FAM_M05e_Lavaplatos; Nota clave: MB3; Número OmniClass: 23.40.20.00; Título OmniClass: General Furniture and Specialties
Type - Materiales y acabados - Interiores: Melamina Puertas Mueble de Cocina; Tablero chapa: Melamina Puertas Mueble de Cocina
Pset_FurnitureTypeCommon - Status: NEW
Otros - Familia: GDV_FAM_M05e_Lavaplatos; Familia y tipo: GDV_FAM_M05e_Lavaplatos: GDV_FAM_M05e_Lavaplatos; ID de tipo: 673382; Tipo: GDV_FAM_M05e_Lavaplatos
Restricciones - Nivel: NOG_PISO 1; Se mueve con elementos cercanos: no; Anfitrión: Suelo : SIP e=210mm; Desfase desde el anfitrión: 2 cm; Elevación desde el nivel: 23 cm
Datos - NDI: NDI-1
Cotas - Alto gola artesanal: 3 cm; Alto total módulo: 88 cm; alto zócalo: 7 cm; Ancho módulo: 120 cm; Área: 3.04804 m2; Espesor módulo base: 1.8 cm; Espesor puerta: 1.8 cm; Profundidad módulo: 58 cm; Profundidad zócalo: 5 cm; Volumen: 0.0507162 m3
Proceso por fases - Fase de creación: New Construction

# IfcFurnishingElement: OGS-FAM-COCINA-BASE-1PUERTA:OGS-FAM-COCINA-BASE-1PUERTA (2)
In: 4
Type - Material: Tirador, <Unnamed>, Damp-proofing, Melamina Puertas Mueble de Cocina, Melamina Muebles Cocina, Durolac
Type - Otros - Categoría: Mobiliario; Nombre de familia: OGS-FAM-COCINA-BASE-1PUERTA
Type - Restricciones - Elevación por defecto: 0 cm
Type - Cotas - ancho total: 60 cm; Distancia para tirador: 3 cm; h total: 88 cm; h zocalo: 7 cm; profundidad total: 58 cm; Zocalo retranqueo: 5 cm
Type - Datos de identidad - Descripción: Mueble base de cocina 1 puerta, melamina.; Marca de tipo: MB1; Nombre de tipo: OGS-FAM-COCINA-BASE-1PUERTA; Nota clave: MB1; Número OmniClass: 23.40.20.00; Título OmniClass: General Furniture and Specialties
Pset_FurnitureTypeCommon - Status: NEW
Otros - Apertura de puertas: no; Familia: OGS-FAM-COCINA-BASE-1PUERTA; Familia y tipo: OGS-FAM-COCINA-BASE-1PUERTA: OGS-FAM-COCINA-BASE-1PUERTA; ID de tipo: 659115; Tipo: OGS-FAM-COCINA-BASE-1PUERTA
Restricciones - Nivel: NOG_PISO 1; Se mueve con elementos cercanos: no; Anfitrión: Nivel : NOG_PISO 1; Desfase desde el anfitrión: 23 cm; Elevación desde el nivel: 23 cm
Datos - NDI: NDI-1
Cotas - Área: 2.93553 m2; Volumen: 0.0370785 m3
Materiales y acabados - Durolac: Durolac; Melamina12mm: Melamina Muebles Cocina; Puerta: Melamina Puertas Mueble de Cocina; Zocalo: Damp-proofing
Proceso por fases - Fase de creación: New Construction
Name (OGS-FAM-COCINA-BASE-1PUERTA:OGS-FAM-COCINA-BASE-1PUERTA:...)
659108
668028

# IfcFurnishingElement: OGS-FAM-COCINA-BASE-1PUERTA:OGS-FAM-COCINA-BASE-1PUERTA ajuste (2)
In: 4
Type - Material: Tirador, <Unnamed>, Damp-proofing, Melamina Puertas Mueble de Cocina, Melamina Muebles Cocina, Durolac
Type - Otros - Categoría: Mobiliario; Nombre de familia: OGS-FAM-COCINA-BASE-1PUERTA
Type - Restricciones - Elevación por defecto: 0 cm
Type - Cotas - ancho total: 30 cm; Distancia para tirador: 3 cm; h total: 88 cm; h zocalo: 7 cm; profundidad total: 58 cm; Zocalo retranqueo: 5 cm
Type - Datos de identidad - Descripción: Mueble base de cocina 1 puerta (variante de ajuste), melamina.; Marca de tipo: MB2; Nombre de tipo: OGS-FAM-COCINA-BASE-1PUERTA ajuste; Nota clave: MB2; Número OmniClass: 23.40.20.00; Título OmniClass: General Furniture and Specialties
Pset_FurnitureTypeCommon - Status: NEW
Otros - Apertura de puertas: no; Familia: OGS-FAM-COCINA-BASE-1PUERTA; Familia y tipo: OGS-FAM-COCINA-BASE-1PUERTA: OGS-FAM-COCINA-BASE-1PUERTA ajuste; ID de tipo: 668112; Tipo: OGS-FAM-COCINA-BASE-1PUERTA ajuste
Restricciones - Nivel: NOG_PISO 1; Se mueve con elementos cercanos: no; Anfitrión: Nivel : NOG_PISO 1; Desfase desde el anfitrión: 23 cm; Elevación desde el nivel: 23 cm
Datos - NDI: NDI-1
Cotas - Área: 1.95663 m2; Volumen: 0.0265282 m3
Materiales y acabados - Durolac: Durolac; Melamina12mm: Melamina Muebles Cocina; Puerta: Melamina Puertas Mueble de Cocina; Zocalo: Damp-proofing
Proceso por fases - Fase de creación: New Construction
Name (OGS-FAM-COCINA-BASE-1PUERTA:OGS-FAM-COCINA-BASE-1PUERTA ajuste:...)
668088
668159

# IfcMember: Montante rectangular:70 x 100mm (30)
In: NOG_PISO 1
Type - PredefinedType: MULLION; Material: Aluminio anodizado, antracita
Type - Otros - Categoría: Montantes de muro cortina; Nombre de familia: Montante rectangular
Type - Restricciones - Ángulo: 0 deg; Desfase: 0 cm
Type - Construcción - Grosor: 10 cm; Montante angular: no; Perfil: Perfil de montante de sistema: Rectangular; Posición: Perpendicular a cara
Type - Cotas - Anchura en lado 1: 3.5 cm; Anchura en lado 2: 3.5 cm
Type - Datos de identidad - Descripción: Montante de muro cortina 70x100 mm, aluminio anodizado antracita (Truebond).; Marca de tipo: MO1; Nombre de tipo: 70 x 100mm; Nota clave: MON
Type - Materiales y acabados - Material: Aluminio anodizado, antracita
Otros - Familia: Montante rectangular; Familia y tipo: Montante rectangular: 70 x 100mm; ID de tipo: 591035; Tipo: 70 x 100mm
Restricciones - Nivel: NOG_PISO 1
Datos - NDI: NDI-1
Proceso por fases - Fase de creación: New Construction
Name (Montante rectangular:70 x 100mm:...) | CrossSectionArea (m2) = Área (m2) | NetVolume (m3) = Volumen (m3) | ID de anfitrión | Longitud (cm)
591591 | 0.162975 | 0.0064225 | 591578 | 91.75
591592 | 0.162975 | 0.0064225 | 591578 | 91.75
591593 | 0.162975 | 0.0064225 | 591578 | 91.75
591596 | 0.162975 | 0.0064225 | 591578 | 91.75
591597 | 0.162975 | 0.0064225 | 591578 | 91.75
591598 | 0.162975 | 0.0064225 | 591578 | 91.75
591601 | 0.517 | 0.021 | 591578 | 300
591602 | 0.517 | 0.021 | 591578 | 300
591603 | 0.517 | 0.021 | 591578 | 300
591604 | 0.517 | 0.021 | 591578 | 300
591803 | 0.164817 | 0.00649833 | 591797 | 92.8333
591804 | 0.164817 | 0.00649833 | 591797 | 92.8333
591805 | 0.164817 | 0.00649833 | 591797 | 92.8333
591806 | 0.164817 | 0.00649833 | 591797 | 92.8333
591807 | 0.164817 | 0.00649833 | 591797 | 92.8333
591808 | 0.164817 | 0.00649833 | 591797 | 92.8333
591809 | 0.517 | 0.021 | 591797 | 300
591810 | 0.517 | 0.021 | 591797 | 300
591811 | 0.517 | 0.021 | 591797 | 300
591812 | 0.517 | 0.021 | 591797 | 300
637029 | 0.161133 | 0.00634667 | 637015 | 90.6667
637030 | 0.161133 | 0.00634667 | 637015 | 90.6667
637031 | 0.161133 | 0.00634667 | 637015 | 90.6667
637034 | 0.161133 | 0.00634667 | 637015 | 90.6667
637035 | 0.161133 | 0.00634667 | 637015 | 90.6667
637036 | 0.161133 | 0.00634667 | 637015 | 90.6667
637039 | 0.517 | 0.021 | 637015 | 300
637040 | 0.517 | 0.021 | 637015 | 300
637041 | 0.517 | 0.021 | 637015 | 300
637042 | 0.517 | 0.021 | 637015 | 300

# IfcOpeningElement: Opening (38)
Name | In | Height (cm) | Width (cm) | Categoría
Suelo:SIP e=210mm:579717 | NOG_PISO 1 | 306.5 | 300 | Líneas: <Boceto> | Otros - Voladizo de acero: 0 cm; Voladizo de hormigón: 0 cm; Restricciones - Define altura constante: no; Define pendiente: no; Desfase desde base: 0 cm; Cotas - Longitud: 300 cm; Pendiente: 0.0833333
Suelo:PAV Tipo Madera:580259 | NPT |  |  | Líneas: <Boceto> | Otros - Voladizo de acero: 0 cm; Voladizo de hormigón: 0 cm; Restricciones - Define altura constante: no; Define pendiente: no; Desfase desde base: 0 cm; Cotas - Longitud: 4.5 cm; Pendiente: 0.0833333; BaseQuantities - Area: 15.1045 m2
Muro básico:Panel SiP perimetral 117mm:590260 | NPT | 70 | 11.7 | Ventanas | BaseQuantities - Depth: 145 cm; Otros - Altura de extremo inicial: 161.5 cm; Familia: M_Fixed1; Familia y tipo: M_Fixed1: 145*70; ID de anfitrión: 590636; ID de tipo: 654015; Tipo: 145*70; Restricciones - Nivel: NOG_PISO 1; Altura de antepecho: 91.5 cm; Datos - NDI: NDI-1; Cotas - Área: 1.83745 m2; Volumen: 0.0290748 m3; Datos de identidad - Marca: 29; Proceso por fases - Fase de creación: New Construction
Muro básico:Panel SiP perimetral 117mm:590636 | NPT | 70 | 11.7 | Ventanas | BaseQuantities - Depth: 145 cm; Otros - Altura de extremo inicial: 161.5 cm; Familia: M_Fixed1; Familia y tipo: M_Fixed1: 145*70; ID de anfitrión: 590689; ID de tipo: 654015; Tipo: 145*70; Restricciones - Nivel: NOG_PISO 1; Altura de antepecho: 91.5 cm; Datos - NDI: NDI-1; Cotas - Área: 1.83745 m2; Volumen: 0.0290748 m3; Datos de identidad - Marca: 9; Proceso por fases - Fase de creación: New Construction
Muro básico:Panel SiP perimetral 117mm:590636 | NPT | 70 | 11.7 | Ventanas | BaseQuantities - Depth: 148 cm; Otros - Altura de extremo inicial: 161.5 cm; Familia: M_Fixed1; Familia y tipo: M_Fixed1: 148*70; ID de anfitrión: 590260; ID de tipo: 654347; Tipo: 148*70; Restricciones - Nivel: NOG_PISO 1; Altura de antepecho: 91.5 cm; Datos - NDI: NDI-1; Cotas - Área: 1.87039 m2; Volumen: 0.0295731 m3; Datos de identidad - Marca: 25; Proceso por fases - Fase de creación: New Construction
Suelo:SIP e=210mm:579717 | NOG_SIP Cara Superior | 306.35 | 300 | Líneas: <Boceto> | Otros - Voladizo de acero: 0 cm; Voladizo de hormigón: 0 cm; Restricciones - Define altura constante: no; Define pendiente: no; Desfase desde base: 0 cm; Cotas - Longitud: 300 cm; Pendiente: 0.0833333
Muro básico:Fachada Revestimiento:603639 | NOG_PISO 1 | 85 | 198 | Líneas: <Boceto> | Cotas - Longitud: 85 cm
2 x Muro básico:Fachada Revestimiento:603639 | NOG_PISO 1 | 290 | 70 | Líneas: <Boceto> | Cotas - Longitud: 290 cm
Muro básico:Fachada Revestimiento:603639 | NOG_PISO 1 | 60 | 307 | Líneas: <Boceto> | Cotas - Longitud: 60 cm
Muro básico:Fachada Revestimiento:603639 | NOG_PISO 1 | 592.224 | 70 | Líneas: <Boceto> | Cotas - Longitud: 592.224 cm
Muro básico:Fachada Revestimiento:603639 | NOG_PISO 1 | 70 | 444 | Líneas: <Boceto> | Cotas - Longitud: 70 cm
Suelo:Cubierta Cocina:668186 | NOG_PISO 1 | 81 | 44 | Líneas: <Boceto> | Otros - Voladizo de acero: 0 cm; Voladizo de hormigón: 0 cm; Restricciones - Define altura constante: no; Define pendiente: no; Desfase desde base: 0 cm; Cotas - Longitud: 44 cm; Pendiente: 0.0833333
Muro básico:Rev Volcanita ST + Melamina tipo madera:587698 | NPT | 592.224 | 70 | Líneas: <Boceto> | Cotas - Longitud: 592.224 cm
Muro básico:Rev Porcelanato ZH:680725 | NOG_PISO 1 | 218 | 85 | Líneas: <Boceto> | Cotas - Longitud: 218 cm
Muro básico:Rev Porcelanato ZH:680725 | NOG_PISO 1 | 218 | 86 | Líneas: <Boceto> | Cotas - Longitud: 218 cm
Muro básico:Rev Volcanita ST + Melamina tipo madera:587698 | NPT | 290 | 70 | Líneas: <Boceto> | Cotas - Longitud: 290 cm
Muro básico:Rev Volcanita ST + Melamina tipo madera:587698 | NPT | 197 | 85 | Líneas: <Boceto> | Cotas - Longitud: 197 cm
Muro básico:Rev Volcanita ST + Melamina tipo madera:587698 | NPT | 70 | 288.6 | Líneas: <Boceto> | Cotas - Longitud: 288.6 cm
Muro básico:Rev Volcanita ST + Melamina tipo madera:587698 | NPT | 70 | 443.1 | Líneas: <Boceto> | Cotas - Longitud: 443.1 cm
2 x Muro básico:Rev Volcanita ST + Melamina tipo madera:587698 | NPT | 85 | 196 | Líneas: <Boceto> | Cotas - Longitud: 196 cm
M_Fixed1:153.5*60:654432:1 | NPT | 153.5 | 60 | BaseQuantities - Depth: 11.7 cm
M_Fixed1:153.5*60:654688:1 | NPT | 153.5 | 60 | BaseQuantities - Depth: 11.7 cm
M_Fixed1:148*70:655333:1 | NPT | 70 | 148 | BaseQuantities - Depth: 11.7 cm
M_Fixed1:148*70:655479:1 | NPT | 70 | 148 | BaseQuantities - Depth: 11.7 cm
M_Fixed1:148*70:655567:1 | NPT | 70 | 148 | BaseQuantities - Depth: 11.7 cm
M_Fixed1:148*70:655576:1 | NPT | 70 | 148 | BaseQuantities - Depth: 11.7 cm
M_Fixed1:148*70:654091:1 | NPT | 148 | 70 | BaseQuantities - Depth: 11.7 cm
M_Fixed1:148*70:654401:1 | NPT | 148 | 70 | BaseQuantities - Depth: 11.7 cm
M_Fixed1:148*70:654392:1 | NPT | 148 | 70 | BaseQuantities - Depth: 11.7 cm
M_Fixed1:145*70:655928:1 | NPT | 145 | 70 | BaseQuantities - Depth: 11.7 cm
M_Fixed1:145*70:656034:1 | NPT | 145 | 70 | BaseQuantities - Depth: 11.7 cm
M_Fixed1:145*70:653817:1 | NPT | 70 | 145 | BaseQuantities - Depth: 11.7 cm
M_Fixed1:145*70:654301:1 | NPT | 70 | 145 | BaseQuantities - Depth: 11.7 cm
TBC-P-PuertaSimpleMadera:TBC_ARQ_PuertaSimple_P85:603907:1 | NPT | 198 | 85 | BaseQuantities - Depth: 11.7 cm
TBC-P-PuertaSimpleMadera:TBC-ARQ-Puerta Simple Madera-P1-0.75x2.10:625171:1 | NOG_PISO 1 | 197 | 85 | BaseQuantities - Depth: 9 cm
TBC-P-PuertaSimpleMadera:TBC-ARQ-Puerta Simple Madera-P1-0.75x2.10:625263:1 | NOG_PISO 1 | 197 | 85 | BaseQuantities - Depth: 9 cm

# IfcPlate: System Panel:Termopanel 2 (9)
In: NOG_PISO 1
Type - PredefinedType: CURTAIN_PANEL; Material: Glass
Type - Otros - Categoría: Paneles de muro cortina; Nombre de familia: System Panel
Type - Restricciones - Desfase: 0 cm
Type - Cotas - Grosor: 2.5 cm
Type - Datos de identidad - Descripción: Vidrio DVH (termopanel) Low-E 24 mm con gas argon.; Marca de tipo: PV1; Nombre de tipo: Termopanel 2; Nota clave: TPA
Type - Materiales y acabados - Material: Glass
Type - Propiedades analíticas - Definir propiedades térmicas por: Tipo esquemático; Construcción analítica: <Ninguno>
Otros - Familia: System Panel; Familia y tipo: System Panel: Termopanel 2; ID de tipo: 591032; Tipo: Termopanel 2
Restricciones - Nivel: NOG_PISO 1
Datos - NDI: NDI-1
Cotas - Altura: 286 cm
Proceso por fases - Fase de creación: New Construction
Name (System Panel:Termopanel 2:...) | NetVolume (m3) = Volumen (m3) | ID de anfitrión | Anchura (cm) | Área (m2)
591579 | 0.0656013 | 591578 | 91.75 | 2.62405
591582 | 0.0656013 | 591578 | 91.75 | 2.62405
591584 | 0.0656013 | 591578 | 91.75 | 2.62405
591798 | 0.0663758 | 591797 | 92.8333 | 2.65503
591800 | 0.0663758 | 591797 | 92.8333 | 2.65503
591802 | 0.0663758 | 591797 | 92.8333 | 2.65503
637016 | 0.0648267 | 637015 | 90.6667 | 2.59307
637021 | 0.0648267 | 637015 | 90.6667 | 2.59307
637023 | 0.0648267 | 637015 | 90.6667 | 2.59307

# IfcRoof: Cubierta básica:Cubierta Cubiculo, Cubierta básica:Cubierta Cubiculo:599002
In: NOG_Pilares Cara Superior
Type - Otros - Categoría: Cubiertas; Nombre de familia: Cubierta básica
Type - Construcción - Grosor predeterminado: 3 cm
Type - Gráficos - Color de relleno de detalle bajo: 0; Patrón de relleno de detalle bajo: <Relleno uniforme>
Type - Datos de identidad - Descripción: Cubierta: panel micro-ondulado 0,35 mm RAL 9017 (Imperial) + barrera de humedad + OSB 18 mm.; Marca de tipo: CU1; Nombre de tipo: Cubierta Cubiculo; Nota clave: CUB
Type - Propiedades analíticas - Absortancia: 0.7; Aspereza: 3
Material: Panel Micro Ondulado Negro 1.2 cm, M_OSB 18mm 1.8 cm
Pset_RoofCommon - IsExternal: yes; FireRating: S/I
BaseQuantities - GrossArea: 122.039 m2; NetArea: 122.039 m2
Otros - Familia: Cubierta básica; Familia y tipo: Cubierta básica: Cubierta Cubiculo; ID de tipo: 599229; Tipo: Cubierta Cubiculo
Restricciones - Delimitación de habitación: yes; Relacionado con masa: no; Desfase de nivel: 0 cm; Final de extrusión: -1008 cm; Inicio de extrusión: 95 cm; Nivel de referencia: NOG_Pilares Cara Superior; Plano de trabajo: Arauco Hilam Viga : Hilam Viga 65x228 mm
Construcción - Corte de alero: Corte a plomo; Profundidad de imposta: 0 cm
Datos - NDI: NDI-1
Cotas - Área: 122.039 m2; Grosor: 3 cm; Pendiente: 0.052521; Volumen: 3.66116 m3
Proceso por fases - Fase de creación: New Construction

# IfcSlab: Suelo:Cubierta Cocina, Suelo:Cubierta Cocina:668173
In: NOG_PISO 1
Type - PredefinedType: FLOOR; Material: Cubierta cocina 2 cm
Type - Otros - Categoría: Suelos; Nombre de familia: Suelo
Type - Construcción - Función: Interior; Grosor predeterminado: 2 cm
Type - Gráficos - Color de relleno de detalle bajo: 0
Type - Datos de identidad - Descripción: Cubierta de cocina Silestone Bohemian Flame (Cosentino), 20 mm.; Marca de tipo: CU2; Nombre de tipo: Cubierta Cocina; Nota clave: CCO
Type - Propiedades analíticas - Absortancia: 0.7; Aspereza: 3
Pset_SlabCommon - IsExternal: yes; FireRating: S/I; Status: NEW
BaseQuantities - Width: 60 cm; Perimeter: 733 cm; GrossArea: 1.839 m2; NetArea: 1.4826 m2; GrossVolume: 0.03678 m3; NetVolume: 0.029652 m3
Otros - Familia: Suelo; Familia y tipo: Suelo: Cubierta Cocina; ID de tipo: 668186; Tipo: Cubierta Cocina
Restricciones - Delimitación de habitación: yes; Nivel: NOG_PISO 1; Relacionado con masa: no; Desfase de altura desde nivel: 113 cm
Datos - NDI: NDI-1
Cotas - Área: 1.4826 m2; Elevación en parte inferior: 211 cm; Elevación en parte inferior de núcleo: 211 cm; Elevación en parte superior: 213 cm; Elevación en parte superior de núcleo: 213 cm; Grosor: 2 cm; Perímetro: 983 cm; Volumen: 0.029652 m3
Datos de identidad - Tiene asociación: no
Proceso por fases - Fase de creación: New Construction
Estructura - Estructura: no

# IfcSlab: Suelo:PAV Tipo Madera, Suelo:PAV Tipo Madera:580278
In: NPT
Type - PredefinedType: FLOOR; Material: Pav Tipo Madera 2 cm
Type - Otros - Categoría: Suelos; Nombre de familia: Suelo
Type - Construcción - Función: Interior; Grosor predeterminado: 2 cm
Type - Gráficos - Color de relleno de detalle bajo: 0
Type - Datos de identidad - Descripción: Piso fotolaminado Krono Super Natural (ATIKA) 8 mm AC4, sobre manta acustica bajo piso flotante. Barrera de vapor de polietileno 0,2 mm continua bajo la manta acustica, con traslapes sellados.; Marca de tipo: PA1; Nombre de tipo: PAV Tipo Madera; Nota clave: PFL
Type - Propiedades analíticas - Absortancia: 0.7; Aspereza: 3
Pset_SlabCommon - IsExternal: no; FireRating: S/I; Status: NEW
BaseQuantities - Perimeter: 3747 cm; GrossArea: 76.7876 m2; NetArea: 61.6831 m2; GrossVolume: 1.53575 m3; NetVolume: 1.23366 m3
Otros - Familia: Suelo; Familia y tipo: Suelo: PAV Tipo Madera; ID de tipo: 580259; Tipo: PAV Tipo Madera
Restricciones - Delimitación de habitación: yes; Relacionado con masa: no; Desfase de altura desde nivel: 0 cm; Nivel: NPT
Datos - NDI: NDI-1
Cotas - Área: 61.6831 m2; Elevación en parte inferior: 121 cm; Elevación en parte inferior de núcleo: 121 cm; Elevación en parte superior: 123 cm; Elevación en parte superior de núcleo: 123 cm; Grosor: 2 cm; Perímetro: 5392.3 cm; Volumen: 1.23366 m3
Datos de identidad - Tiene asociación: no
Proceso por fases - Fase de creación: New Construction
Estructura - Estructura: no

# IfcSlab: Suelo:PAV Tipo Porcelanato 1 (2)
In: NPT
Type - PredefinedType: FLOOR; Material: Pav Tipo Porcenalanato 1 2 cm
Type - Otros - Categoría: Suelos; Nombre de familia: Suelo
Type - Construcción - Función: Interior; Grosor predeterminado: 2 cm
Type - Gráficos - Color de relleno de detalle bajo: 0
Type - Datos de identidad - Descripción: Porcelanato antideslizante Techtonique Platinum Mate 60x60 cm (MK), zona humeda.; Marca de tipo: PA2; Nombre de tipo: PAV Tipo Porcelanato 1; Nota clave: PPO
Type - Propiedades analíticas - Absortancia: 0.7; Aspereza: 3
Pset_SlabCommon - IsExternal: no; FireRating: S/I; Status: NEW
BaseQuantities - Perimeter: 581.7 cm; GrossArea: 2.0837 m2; NetArea: 4.16741 m2; GrossVolume: 0.0416741 m3; NetVolume: 0.0833481 m3
Otros - Familia: Suelo; Familia y tipo: Suelo: PAV Tipo Porcelanato 1; ID de tipo: 580501; Tipo: PAV Tipo Porcelanato 1
Restricciones - Delimitación de habitación: yes; Relacionado con masa: no; Desfase de altura desde nivel: 0 cm; Nivel: NPT
Datos - NDI: NDI-1
Cotas - Área: 4.16741 m2; Elevación en parte inferior: 121 cm; Elevación en parte inferior de núcleo: 121 cm; Elevación en parte superior: 123 cm; Elevación en parte superior de núcleo: 123 cm; Grosor: 2 cm; Perímetro: 1163.4 cm; Volumen: 0.0833481 m3
Datos de identidad - Tiene asociación: no
Proceso por fases - Fase de creación: New Construction
Estructura - Estructura: no
Name (Suelo:PAV Tipo Porcelanato 1:...)
657012
657012:2

# IfcSlab: Suelo:SIP e=210mm (2)
Type - PredefinedType: FLOOR; Material: SIP OSB 1.1 cm, SIP Aislamiento - Poliestireno expandido 18.8 cm, SIP OSB 1.1 cm
Type - Otros - Categoría: Suelos; Nombre de familia: Suelo
Type - Construcción - Función: Interior; Grosor predeterminado: 21 cm
Type - Gráficos - Color de relleno de detalle bajo: 0
Type - Datos de identidad - Descripción: Panel SIP 210 mm (piso ventilado y cielo termico). Barrera de vapor de polietileno 0,2 mm continua en la cara interior, con traslapes sellados. En el piso va bajo la manta acustica; en el cielo, tras la volcanita.; Marca de tipo: L1; Nombre de tipo: SIP e=210mm; Nota clave: SPL; URL: https://kitpanels.cl/wp-content/uploads/2023/05/ficha210-1.pdf
Type - Propiedades analíticas - Absortancia: 0.7; Aspereza: 3
Pset_SlabCommon - FireRating: S/I; IsExternal: yes; ThermalTransmittance: 0.209; Status: NEW
Otros - Familia: Suelo; Familia y tipo: Suelo: SIP e=210mm; ID de tipo: 579717; Tipo: SIP e=210mm
Restricciones - Delimitación de habitación: yes; Desfase de altura desde nivel: 21 cm; Relacionado con masa: no
Datos - NDI: NDI-1
Cotas - Grosor: 21 cm
Datos de identidad - Tiene asociación: no
Proceso por fases - Fase de creación: New Construction
Estructura - Estructura: no
Name (Suelo:SIP e=210mm:...) | In | Width (cm) | Perimeter (cm) | GrossArea (m2) | NetArea (m2) = Área (m2) | GrossVolume (m3) | NetVolume (m3) = Volumen (m3) | Nivel | Elevación en parte inferior (cm) | Elevación en parte inferior de núcleo (cm) | Elevación en parte superior (cm) | Elevación en parte superior de núcleo (cm) | Perímetro (cm)
579704 | NOG_PISO 1 | 900 | 3600 | 81 | 71.805 | 17.01 | 15.079 | NOG_PISO 1 | 100 | 101.1 | 121 | 119.9 | 4813
592789 | NOG_SIP Cara Superior | 900.3 | 3601.2 | 81.054 | 71.8635 | 17.0213 | 15.0913 | NOG_SIP Cara Superior | 421 | 422.1 | 442 | 440.9 | 4813.9

# IfcWallStandardCase: Muro básico:Fachada Revestimiento (4)
In: NOG_PISO 1
Type - PredefinedType: STANDARD; Material: Revestimiento Exterior Muros 3 cm, Exterior revestimiento vertical aire 2 cm
Type - Otros - Categoría: Muros; Nombre de familia: Muro básico
Type - Construcción - Función: Interior; Anchura: 5 cm; Envolvente en extremos: Exterior; Envolvente en inserciones: Exterior
Type - Gráficos - Color de relleno de detalle bajo: 0
Type - Datos de identidad - Descripción: Panel emballetado de acero 50 mm, ancho util 475 mm, color negro mate (Comercial Arratia). Zn-Al-Mg 0,5 mm; camara de aire ventilada 20 mm.; Marca de tipo: M3; Nombre de tipo: Fachada Revestimiento; Nota clave: FAC; URL: https://www.arratia.cl/wp-content/uploads/2021/12/Ficha-Tecnica_Emballetados_compressed.pdf
Type - Propiedades analíticas - Absortancia: 0.7; Aspereza: 3
BaseQuantities - Height: 342 cm; Length: 905 cm; Width: 5 cm; GrossFootprintArea: 0.4525 m2; GrossVolume: 1.54755 m3; GrossSideArea: 30.951 m2
Pset_WallCommon - IsExternal: yes; FireRating: S/I; Status: NEW
Otros - Familia: Muro básico; Familia y tipo: Muro básico: Fachada Revestimiento; ID de tipo: 603639; Tipo: Fachada Revestimiento
Restricciones - Desfase de base: 0 cm; Delimitación de habitación: yes; Relacionado con masa: no; Distancia de extensión de base: 0 cm; Distancia de extensión superior: 0 cm; La base está enlazada: no; La parte superior está enlazada: no; Restricción superior: Hasta nivel: NOG_SIP Cara Superior; Restricción de base: NOG_PISO 1; Altura desconectada: 342 cm; Desfase superior: 21 cm; Línea de ubicación: Cara de acabado: Interior
Datos - NDI: NDI-1
Cotas - Longitud: 905 cm
Proceso por fases - Fase de creación: New Construction
Estructura - Estructura: no; Uso estructural: No portante
Definición de sección transversal - Sección transversal: Vertical
Name (Muro básico:Fachada Revestimiento:...) | NetSideArea (m2) = Área (m2) | NetVolume (m3) = Volumen (m3)
603783 | 27.238 | 1.3619
603784 | 29.109 | 1.45545
603785 | 26.8054 | 1.34027
603786 | 25.813 | 1.29065

# IfcWallStandardCase: Muro básico:Panel SiP Interior 90mm (6)
In: NOG_PISO 1
Type - PredefinedType: STANDARD; Material: SIP OSB 1.1 cm, SIP Aislamiento - Poliestireno expandido 6.8 cm, SIP OSB 1.1 cm
Type - Otros - Categoría: Muros; Nombre de familia: Muro básico
Type - Construcción - Función: Interior; Envolvente en extremos: Ninguno; Envolvente en inserciones: Sin envolvente; Anchura: 9 cm
Type - Gráficos - Color de relleno de detalle bajo: 0
Type - Datos de identidad - Descripción: Tabique interior: panel SIP interior 90 mm (OSB 11 + EPS 68 + OSB 11), KitPanels. Keynote de tipo SPI.; Marca de tipo: M2; Nombre de tipo: Panel SiP Interior 90mm; Nota clave: SPI
Type - Materiales y acabados - Material estructural: SIP Aislamiento - Poliestireno expandido
Type - Propiedades analíticas - Absortancia: 0.7; Aspereza: 3
BaseQuantities - Height: 300 cm; Width: 9 cm
Pset_WallCommon - IsExternal: no; FireRating: S/I; Status: NEW
Otros - Familia: Muro básico; Familia y tipo: Muro básico: Panel SiP Interior 90mm; ID de tipo: 624236; Tipo: Panel SiP Interior 90mm
Restricciones - Delimitación de habitación: yes; Relacionado con masa: no; Desfase superior: 0 cm; Distancia de extensión de base: 0 cm; Distancia de extensión superior: 0 cm; La base está enlazada: no; La parte superior está enlazada: no; Línea de ubicación: Eje del núcleo; Restricción de base: NOG_PISO 1; Altura desconectada: 300 cm; Desfase de base: 21 cm
Datos - NDI: NDI-1
Proceso por fases - Fase de creación: New Construction
Estructura - Estructura: no; Uso estructural: No portante
Definición de sección transversal - Sección transversal: Vertical
Name (Muro básico:Panel SiP Interior 90mm:...) | Length (cm) | GrossFootprintArea (m2) | GrossVolume (m3) | GrossSideArea (m2) | NetSideArea (m2) = Área (m2) | NetVolume (m3) = Volumen (m3) | Longitud (cm)
624334 | 158.85 | 0.142965 | 0.428895 | 4.7655 | 4.7655 | 0.428895 | 154.35
624915 | 282 | 0.2538 | 0.7614 | 8.46 | 5.111 | 0.45999 | 291
625051 | 150 | 0.135 | 0.405 | 4.5 | 4.5 | 0.405 | 154.5
625261 | 158.85 | 0.142965 | 0.428895 | 4.7655 | 4.7655 | 0.428895 | 158.85
639430 | 59.85 | 0.053865 | 0.161595 | 1.7955 | 1.7955 | 0.161595 | 59.85
650639 | 59.85 | 0.053865 | 0.161595 | 1.7955 | 1.7955 | 0.161595 | 59.85

# IfcWallStandardCase: Muro básico:Panel SiP perimetral 117mm (5)
Type - PredefinedType: STANDARD; Material: SIP OSB 1.1 cm, SIP Aislamiento - Poliestireno expandido 9.5 cm, SIP OSB 1.1 cm
Type - Otros - Categoría: Muros; Nombre de familia: Muro básico
Type - Construcción - Función: Interior; Anchura: 11.7 cm; Envolvente en extremos: Ninguno; Envolvente en inserciones: Sin envolvente
Type - Gráficos - Color de relleno de detalle bajo: 0
Type - Datos de identidad - Descripción: Muro exterior: panel SIP perimetral. Barrera de vapor de polietileno 0,2 mm continua en la cara interior, con traslapes sellados. El OSB del panel debe informar factor de resistencia al vapor mu maximo 150 (KitPanels).; Marca de tipo: M1; Nombre de tipo: Panel SiP perimetral 117mm; Nota clave: SPP; URL: https://kitpanels.cl/wp-content/uploads/2023/05/ficha116-1.pdf
Type - Materiales y acabados - Material estructural: SIP Aislamiento - Poliestireno expandido
Type - Propiedades analíticas - Absortancia: 0.7; Aspereza: 3
BaseQuantities - Height: 300 cm; Width: 11.7 cm
Pset_WallCommon - IsExternal: yes; FireRating: S/I; ThermalTransmittance: 0.384; Status: NEW
Otros - Familia: Muro básico; Familia y tipo: Muro básico: Panel SiP perimetral 117mm; ID de tipo: 590015; Tipo: Panel SiP perimetral 117mm
Restricciones - Delimitación de habitación: yes; Relacionado con masa: no; Desfase superior: 0 cm; Altura desconectada: 300 cm; Distancia de extensión de base: 0 cm; Distancia de extensión superior: 0 cm; La base está enlazada: no; La parte superior está enlazada: no
Datos - NDI: NDI-1
Proceso por fases - Fase de creación: New Construction
Estructura - Estructura: no; Uso estructural: No portante
Definición de sección transversal - Sección transversal: Vertical
Name (Muro básico:Panel SiP perimetral 117mm:...) | In | Length (cm) | GrossFootprintArea (m2) | GrossVolume (m3) | GrossSideArea (m2) | NetSideArea (m2) = Área (m2) | NetVolume (m3) = Volumen (m3) | Desfase de base (cm) | Línea de ubicación | Restricción de base | Restricción superior | Longitud (cm)
590014 | NPT | 900.3 | 1.05335 | 3.16005 | 27.009 | 25.17 | 2.94489 | -2 | Eje del núcleo | NPT | Hasta nivel: NOG_SIP Cara Superior | 888.6 | Datos de identidad - Comentarios: NDI-PERSIST-TEST-151241
590260 | NPT | 876.9 | 1.02597 | 2.83562 | 24.2361 | 22.1641 | 2.59319 | -2 | Eje del núcleo | NPT | Hasta nivel: NOG_SIP Cara Superior | 888.6
590636 | NPT | 900.3 | 1.05335 | 3.16005 | 27.009 | 21.871 | 2.55866 | -2 | Eje del núcleo | NPT | Hasta nivel: NOG_SIP Cara Superior | 888.6
590689 | NPT | 876.9 | 1.02597 | 2.84053 | 24.2781 | 22.5951 | 2.64362 | -2 | Eje del núcleo | NPT | Hasta nivel: NOG_SIP Cara Superior | 888.6
591007 | NOG_PISO 1 | 300 | 0.351 | 1.053 | 9 | 9 | 1.053 | 21 | Eje del muro | NOG_PISO 1 |  | 300 | Datos de identidad - Marca: V1

# IfcWallStandardCase: Muro básico:Retorno Cubierta cocina, Muro básico:Retorno Cubierta cocina:680423
In: NOG_PISO 1
Type - PredefinedType: STANDARD; Material: Retorno Cubierta cocina 1 cm
Type - Otros - Categoría: Muros; Nombre de familia: Muro básico
Type - Construcción - Función: Interior; Envolvente en extremos: Ninguno; Envolvente en inserciones: Sin envolvente; Anchura: 1 cm
Type - Gráficos - Color de relleno de detalle bajo: 0
Type - Datos de identidad - Descripción: Retorno de cubierta de cocina Silestone Bohemian Flame (Cosentino).; Marca de tipo: M6; Nombre de tipo: Retorno Cubierta cocina; Nota clave: RCC
Type - Propiedades analíticas - Absortancia: 0.7; Aspereza: 3
BaseQuantities - Height: 10 cm; Length: 301.5 cm; Width: 1 cm; GrossFootprintArea: 0.03015 m2; GrossVolume: 0.003015 m3; GrossSideArea: 0.3015 m2; NetSideArea: 0.3015 m2; NetVolume: 0.003015 m3
Pset_WallCommon - FireRating: S/I; Status: NEW
Otros - Familia: Muro básico; Familia y tipo: Muro básico: Retorno Cubierta cocina; ID de tipo: 680426; Tipo: Retorno Cubierta cocina
Restricciones - Delimitación de habitación: yes; Relacionado con masa: no; Desfase superior: 0 cm; Distancia de extensión de base: 0 cm; Distancia de extensión superior: 0 cm; La base está enlazada: no; La parte superior está enlazada: no; Línea de ubicación: Eje del núcleo; Restricción de base: NOG_PISO 1; Altura desconectada: 10 cm; Desfase de base: 113 cm
Datos - NDI: NDI-1
Cotas - Área: 0.3015 m2; Longitud: 301.5 cm; Volumen: 0.003015 m3
Proceso por fases - Fase de creación: New Construction
Estructura - Estructura: no; Uso estructural: No portante
Definición de sección transversal - Sección transversal: Vertical

# IfcWallStandardCase: Muro básico:Rev Porcelanato ZH (8)
Type - PredefinedType: STANDARD; Material: Volcanita ZH 1.25 cm, Rev Porcelanato ZH 1.75 cm
Type - Otros - Categoría: Muros; Nombre de familia: Muro básico
Type - Construcción - Función: Interior; Envolvente en extremos: Ninguno; Envolvente en inserciones: Sin envolvente; Anchura: 3 cm
Type - Gráficos - Color de relleno de detalle bajo: 0
Type - Datos de identidad - Descripción: Volcanita ZH 12,5 mm + porcelanato antideslizante Techtonique Platinum Mate 60x60 cm (MK).; Marca de tipo: M5; Nombre de tipo: Rev Porcelanato ZH; Nota clave: RHU
Type - Propiedades analíticas - Absortancia: 0.7; Aspereza: 3
BaseQuantities - Width: 3 cm
Pset_WallCommon - IsExternal: no; FireRating: S/I; Status: NEW
Otros - Familia: Muro básico; Familia y tipo: Muro básico: Rev Porcelanato ZH; ID de tipo: 680725; Tipo: Rev Porcelanato ZH
Restricciones - Delimitación de habitación: yes; Relacionado con masa: no; Desfase superior: 0 cm; Distancia de extensión de base: 0 cm; Distancia de extensión superior: 0 cm; La base está enlazada: no; La parte superior está enlazada: no; Línea de ubicación: Eje del núcleo; Restricción superior: Hasta nivel: NOG_SIP Cara Superior; Desfase de base: 2 cm
Datos - NDI: NDI-1
Proceso por fases - Fase de creación: New Construction
Estructura - Estructura: no; Uso estructural: No portante
Definición de sección transversal - Sección transversal: Vertical
Name (Muro básico:Rev Porcelanato ZH:...) | In | Height (cm) = Altura desconectada (cm) | Length (cm) | GrossFootprintArea (m2) | GrossVolume (m3) = NetVolume (m3) = Volumen (m3) | GrossSideArea (m2) = NetSideArea (m2) = Área (m2) | Restricción de base | Longitud (cm)
680701 | NPT | 296 | 148.8 | 0.04464 | 0.132134 | 4.40448 | NPT | 148.8
681564 | NOG_PISO 1 | 319 | 133.5 | 0.04005 | 0.12776 | 4.25865 | NOG_PISO 1 | 135
681770 | NOG_PISO 1 | 319 | 147.5 | 0.04425 | 0.141157 | 4.70525 | NOG_PISO 1 | 147.5
681909 | NOG_PISO 1 | 319 | 130.5 | 0.03915 | 0.0692985 | 2.30995 | NOG_PISO 1 | 132
682176 | NPT | 296 | 148.8 | 0.04464 | 0.132134 | 4.40448 | NPT | 148.8
682191 | NOG_PISO 1 | 319 | 133.5 | 0.04005 | 0.12776 | 4.25865 | NOG_PISO 1 | 135
682192 | NOG_PISO 1 | 319 | 147 | 0.0441 | 0.140679 | 4.6893 | NOG_PISO 1 | 147
682193 | NOG_PISO 1 | 319 | 131.5 | 0.03945 | 0.0696015 | 2.32005 | NOG_PISO 1 | 133

# IfcWallStandardCase: Muro básico:Rev Volcanita ST + Melamina tipo madera (14)
Type - PredefinedType: STANDARD; Material: Rev Melamina tipo madera 1.5 cm, Volcanita ST 1 cm
Type - Otros - Categoría: Muros; Nombre de familia: Muro básico
Type - Construcción - Función: Interior; Envolvente en extremos: Ninguno; Envolvente en inserciones: Sin envolvente; Anchura: 2.5 cm
Type - Gráficos - Color de relleno de detalle bajo: 0
Type - Datos de identidad - Descripción: Terminacion interior de muro: volcanita ST 10 mm + melamina 15 mm. Barrera de vapor de polietileno 0,2 mm continua tras la volcanita, con traslapes sellados.; Marca de tipo: M4; Nombre de tipo: Rev Volcanita ST + Melamina tipo madera; Nota clave: RSM
Type - Propiedades analíticas - Absortancia: 0.7; Aspereza: 3
BaseQuantities - Width: 2.5 cm
Pset_WallCommon - IsExternal: no; FireRating: S/I; Status: NEW
Otros - Familia: Muro básico; Familia y tipo: Muro básico: Rev Volcanita ST + Melamina tipo madera; ID de tipo: 587698; Tipo: Rev Volcanita ST + Melamina tipo madera
Restricciones - Delimitación de habitación: yes; Relacionado con masa: no; Desfase superior: 0 cm; Distancia de extensión de base: 0 cm; Distancia de extensión superior: 0 cm; La base está enlazada: no; La parte superior está enlazada: no; Línea de ubicación: Eje del núcleo; Restricción superior: Hasta nivel: NOG_SIP Cara Superior; Desfase de base: 1 cm
Datos - NDI: NDI-1
Proceso por fases - Fase de creación: New Construction
Estructura - Estructura: no; Uso estructural: No portante
Definición de sección transversal - Sección transversal: Vertical
Name (Muro básico:Rev Volcanita ST + Melamina tipo madera:...) | In | Height (cm) = Altura desconectada (cm) | Length (cm) | GrossFootprintArea (m2) | GrossVolume (m3) = NetVolume (m3) = Volumen (m3) | GrossSideArea (m2) = NetSideArea (m2) = Área (m2) | Restricción de base | Longitud (cm)
678973 | NPT | 297 | 877.05 | 0.219263 | 0.54757 | 21.9028 | NPT | 877.05
682807 | NPT | 297 | 275.2 | 0.0688 | 0.204336 | 8.17344 | NPT | 273.95
682847 | NPT | 297 | 59.85 | 0.0149625 | 0.0444386 | 1.77755 | NPT | 59.85
682989 | NPT | 297 | 275.2 | 0.0688 | 0.204336 | 8.17344 | NPT | 273.95
682990 | NPT | 297 | 59.85 | 0.0149625 | 0.0444386 | 1.77754 | NPT | 59.85
695739 | NPT | 297 | 877.05 | 0.219263 | 0.558597 | 22.3439 | NPT | 877.05
695986 | NPT | 297 | 873.65 | 0.218413 | 0.520856 | 20.8343 | NPT | 874.9
712840 | NPT | 297 | 157.9 | 0.039475 | 0.117241 | 4.68963 | NPT | 156.65
713439 | NPT | 297 | 11.5 | 0.002875 | 0.00853875 | 0.34155 | NPT | 11.5
713521 | NOG_PISO 1 | 320 | 59.85 | 0.0149625 | 0.04788 | 1.9152 | NOG_PISO 1 | 66.95
714404 | NPT | 297 | 62.35 | 0.0155875 | 0.0462949 | 1.85179 | NPT | 66.95
714450 | NPT | 297 | 9 | 0.00225 | 0.0066825 | 0.2673 | NPT | 11.5
714940 | NPT | 297 | 302.5 | 0.075625 | 0.141306 | 5.65225 | NPT | 302.5
715097 | NPT | 297 | 155.4 | 0.03885 | 0.115384 | 4.61538 | NPT | 156.65

# IfcWindow: M_Fixed1:145*70 (4)
In: NOG_PISO 1
Type - ParameterTakesPrecedence: no; Sizeable: no; Material: Aluminio anodizado, antracita, Glass
Type - Otros(Tipo) - Categoría: Ventanas; Nombre de familia: M_Fixed1
Type - Construcción(Tipo) - Cierre de muro: Por anfitrión
Type - Cotas(Tipo) - Altura: 70 cm; Altura bruta: 0 cm; Anchura: 145 cm; Anchura bruta: 0 cm; Default Sill Height: 91.5 cm; Window Inset: 1.9 cm
Type - Datos de identidad(Tipo) - Descripción: Ventana fija 145x70 cm. Marco aluminio con RPT; vidrio DVH Low-E 24 mm (4/16/4) con gas argon. Uw calculado 2,5 W/m2K (planilla DITEC NCh3137-1, ver EETT Anexo A).; Marca de tipo: V1; Nombre de tipo: 145*70; Nota clave: VF1; Número OmniClass: 23.30.20.17.11; Título OmniClass: Fixed Windows
Type - Materiales y acabados(Tipo) - Frame Exterior Material: Aluminio anodizado, antracita; Frame Interior Material: Aluminio anodizado, antracita; Glass Pane Material: Glass; Sash: Aluminio anodizado, antracita
Type - Propiedades analíticas(Tipo) - Construcción analítica: <Ninguno>; Definir propiedades térmicas por: Tipo esquemático
OverallHeight: 70 cm; OverallWidth: 145 cm
Pset_WindowCommon - IsExternal: yes; FireRating: S/I; ThermalTransmittance: 2.5; Status: NEW
BaseQuantities - Height: 70 cm; Width: 145 cm; Area: 1.015 m2
Otros - Categoría: Ventanas; Familia: M_Fixed1; Familia y tipo: M_Fixed1: 145*70; ID de tipo: 654015; Tipo: 145*70; Altura de extremo inicial: 161.5 cm
Restricciones - Nivel: NOG_PISO 1; Altura de antepecho: 91.5 cm
Datos - NDI: NDI-1
Cotas - Área: 1.83745 m2; Volumen: 0.0290748 m3
Proceso por fases - Fase de creación: New Construction
Name (M_Fixed1:145*70:...) | ID de anfitrión | Marca
653817 | 590689 | 9
654301 | 590689 | 16
655928 | 590636 | 29
656034 | 590636 | 30

# IfcWindow: M_Fixed1:148*70 (7)
In: NOG_PISO 1
Type - ParameterTakesPrecedence: no; Sizeable: no; Material: Aluminio anodizado, antracita, Glass
Type - Otros(Tipo) - Categoría: Ventanas; Nombre de familia: M_Fixed1
Type - Construcción(Tipo) - Cierre de muro: Por anfitrión
Type - Cotas(Tipo) - Altura bruta: 0 cm; Anchura bruta: 0 cm; Altura: 70 cm; Anchura: 148 cm; Default Sill Height: 91.5 cm; Window Inset: 1.9 cm
Type - Datos de identidad(Tipo) - Descripción: Ventana fija 148x70 cm. Marco aluminio con RPT; vidrio DVH Low-E 24 mm (4/16/4) con gas argon. Uw calculado 2,5 W/m2K (planilla DITEC NCh3137-1, ver EETT Anexo A).; Marca de tipo: V2; Nombre de tipo: 148*70; Nota clave: VF2; Número OmniClass: 23.30.20.17.11; Título OmniClass: Fixed Windows
Type - Materiales y acabados(Tipo) - Frame Exterior Material: Aluminio anodizado, antracita; Frame Interior Material: Aluminio anodizado, antracita; Glass Pane Material: Glass; Sash: Aluminio anodizado, antracita
Type - Propiedades analíticas(Tipo) - Definir propiedades térmicas por: Tipo esquemático; Construcción analítica: <Ninguno>
OverallHeight: 70 cm; OverallWidth: 148 cm
Pset_WindowCommon - IsExternal: yes; ThermalTransmittance: 2.5; FireRating: S/I; Status: NEW
BaseQuantities - Height: 70 cm; Width: 148 cm; Area: 1.036 m2
Otros - Categoría: Ventanas; Familia: M_Fixed1; Familia y tipo: M_Fixed1: 148*70; ID de tipo: 654347; Tipo: 148*70; Altura de extremo inicial: 161.5 cm
Restricciones - Nivel: NOG_PISO 1; Altura de antepecho: 91.5 cm
Datos - NDI: NDI-1
Cotas - Área: 1.87039 m2; Volumen: 0.0295731 m3
Proceso por fases - Fase de creación: New Construction
Name (M_Fixed1:148*70:...) | ID de anfitrión | Marca
654091 | 590636 | 12
654392 | 590636 | 17
654401 | 590636 | 18
655333 | 590260 | 25
655479 | 590260 | 26
655567 | 590260 | 27
655576 | 590260 | 28

# IfcWindow: M_Fixed1:153.5*60 (2)
In: NOG_PISO 1
Type - ParameterTakesPrecedence: no; Sizeable: no; Material: Aluminio anodizado, antracita, Glass
Type - Otros - Categoría: Ventanas; Nombre de familia: M_Fixed1
Type - Construcción - Cierre de muro: Por anfitrión
Type - Cotas - Altura bruta: 0 cm; Anchura bruta: 0 cm; Altura: 60 cm; Anchura: 153.5 cm; Default Sill Height: 91.5 cm; Window Inset: 1.9 cm
Type - Datos de identidad - Descripción: Ventana fija 153,5x60 cm. Marco aluminio con RPT; vidrio DVH Low-E 24 mm (4/16/4) con gas argon. Uw calculado 2,6 W/m2K (planilla DITEC NCh3137-1, ver EETT Anexo A).; Marca de tipo: V3; Nombre de tipo: 153.5*60; Nota clave: VF3; Número OmniClass: 23.30.20.17.11; Título OmniClass: Fixed Windows
Type - Materiales y acabados - Frame Exterior Material: Aluminio anodizado, antracita; Frame Interior Material: Aluminio anodizado, antracita; Glass Pane Material: Glass; Sash: Aluminio anodizado, antracita
Type - Propiedades analíticas - Definir propiedades térmicas por: Tipo esquemático; Construcción analítica: <Ninguno>
OverallHeight: 60 cm; OverallWidth: 153.5 cm
Pset_WindowCommon - IsExternal: yes; FireRating: S/I; ThermalTransmittance: 2.6; Status: NEW
BaseQuantities - Height: 60 cm; Width: 153.5 cm; Area: 0.921 m2
Otros - Familia: M_Fixed1; Altura de extremo inicial: 183 cm; Familia y tipo: M_Fixed1: 153.5*60; ID de anfitrión: 590014; ID de tipo: 654520; Tipo: 153.5*60
Restricciones - Nivel: NOG_PISO 1; Altura de antepecho: 123 cm
Datos - NDI: NDI-1
Cotas - Área: 1.73748 m2; Volumen: 0.0278237 m3
Proceso por fases - Fase de creación: New Construction
Name (M_Fixed1:153.5*60:...) | Marca
654432 | 20
654688 | 21
